VERSION 5.8 ;
BUSBITCHARS "[]" ;
DIVIDERCHAR "/" ;

PROPERTYDEFINITIONS
  LAYER LEF58_TYPE STRING ;
  LAYER LEF58_SPACING STRING ;
  LAYER LEF58_WIDTH STRING ;
END PROPERTYDEFINITIONS

UNITS
  DATABASE MICRONS 2000 ;
END UNITS
MANUFACTURINGGRID 0.0005 ;

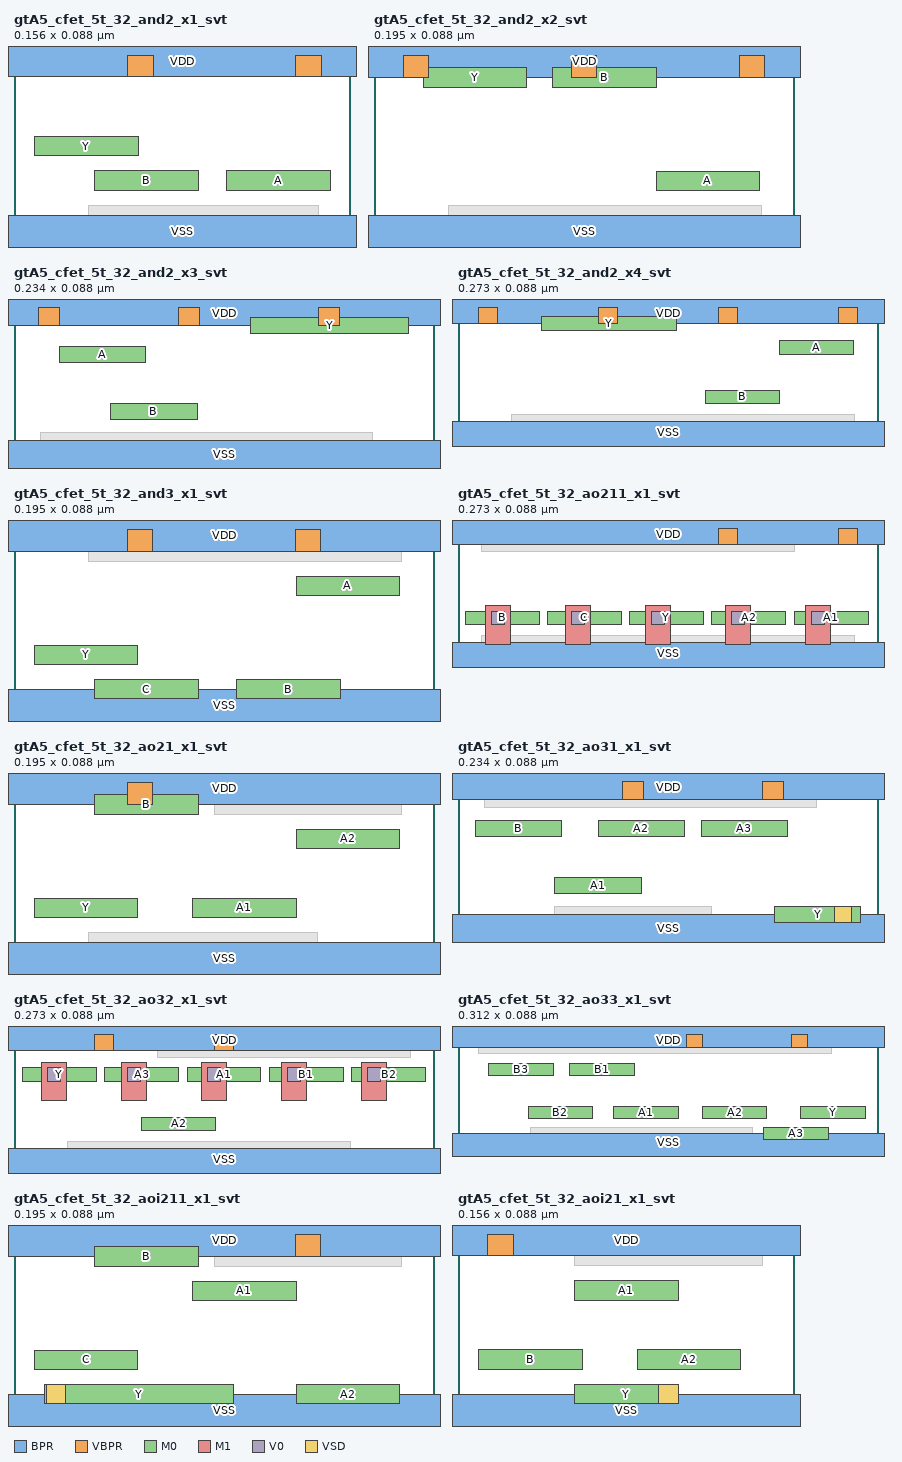
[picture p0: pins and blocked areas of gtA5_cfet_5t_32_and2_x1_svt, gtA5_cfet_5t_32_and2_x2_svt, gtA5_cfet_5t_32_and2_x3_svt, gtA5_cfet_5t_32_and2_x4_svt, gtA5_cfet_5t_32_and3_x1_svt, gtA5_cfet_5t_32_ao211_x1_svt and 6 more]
MACRO gtA5_cfet_5t_32_and2_x1_svt
  CLASS CORE ;
  ORIGIN 0 0 ;
  FOREIGN gtA5_cfet_5t_32_and2_x1_svt 0 0 ;
  SIZE 0.156 BY 0.088 ;
  SYMMETRY X Y ;
  SITE CORESITE_5t_32 ;
  PIN VDD
    DIRECTION INOUT ;
    USE POWER ;
    SHAPE ABUTMENT ;
    PORT
      LAYER BPR ;
        RECT -0.0225 0.076 0.1785 0.1 ;
      LAYER VBPR ;
        RECT 0.0525 0.076 0.0645 0.086 ;
        RECT 0.1305 0.076 0.1425 0.086 ;
    END
  END VDD
  PIN VSS
    DIRECTION INOUT ;
    USE GROUND ;
    SHAPE ABUTMENT ;
    PORT
      LAYER BPR ;
        RECT -0.0225 -0.012 0.1785 0.012 ;
    END
  END VSS
  PIN A
    DIRECTION INPUT ;
    USE SIGNAL ;
    PORT
      LAYER M0 ;
        RECT 0.0985 0.0235 0.1465 0.0325 ;
    END
  END A
  PIN B
    DIRECTION INPUT ;
    USE SIGNAL ;
    PORT
      LAYER M0 ;
        RECT 0.0375 0.0235 0.0855 0.0325 ;
    END
  END B
  PIN Y
    DIRECTION OUTPUT ;
    USE SIGNAL ;
    PORT
      LAYER M0 ;
        RECT 0.0095 0.0395 0.0575 0.0485 ;
    END
  END Y
  OBS
    LAYER VSD ;
      RECT 0.093 0.0075 0.102 0.0165 ;
    LAYER M0 ;
      RECT 0.0345 0.0075 0.141 0.0165 ;
  END
END gtA5_cfet_5t_32_and2_x1_svt

MACRO gtA5_cfet_5t_32_and2_x2_svt
  CLASS CORE ;
  ORIGIN 0 0 ;
  FOREIGN gtA5_cfet_5t_32_and2_x2_svt 0 0 ;
  SIZE 0.195 BY 0.088 ;
  SYMMETRY X Y ;
  SITE CORESITE_5t_32 ;
  PIN VDD
    DIRECTION INOUT ;
    USE POWER ;
    SHAPE ABUTMENT ;
    PORT
      LAYER BPR ;
        RECT -0.0225 0.076 0.2175 0.1 ;
      LAYER VBPR ;
        RECT 0.0135 0.076 0.0255 0.086 ;
        RECT 0.0915 0.076 0.1035 0.086 ;
        RECT 0.1695 0.076 0.1815 0.086 ;
    END
  END VDD
  PIN VSS
    DIRECTION INOUT ;
    USE GROUND ;
    SHAPE ABUTMENT ;
    PORT
      LAYER BPR ;
        RECT -0.0225 -0.012 0.2175 0.012 ;
    END
  END VSS
  PIN A
    DIRECTION INPUT ;
    USE SIGNAL ;
    PORT
      LAYER M0 ;
        RECT 0.131 0.0235 0.179 0.0325 ;
    END
  END A
  PIN B
    DIRECTION INPUT ;
    USE SIGNAL ;
    PORT
      LAYER M0 ;
        RECT 0.083 0.0715 0.131 0.0805 ;
    END
  END B
  PIN Y
    DIRECTION OUTPUT ;
    USE SIGNAL ;
    PORT
      LAYER M0 ;
        RECT 0.023 0.0715 0.071 0.0805 ;
    END
  END Y
  OBS
    LAYER VSD ;
      RECT 0.132 0.0075 0.141 0.0165 ;
    LAYER M0 ;
      RECT 0.0345 0.0075 0.18 0.0165 ;
  END
END gtA5_cfet_5t_32_and2_x2_svt

MACRO gtA5_cfet_5t_32_and2_x3_svt
  CLASS CORE ;
  ORIGIN 0 0 ;
  FOREIGN gtA5_cfet_5t_32_and2_x3_svt 0 0 ;
  SIZE 0.234 BY 0.088 ;
  SYMMETRY X Y ;
  SITE CORESITE_5t_32 ;
  PIN VDD
    DIRECTION INOUT ;
    USE POWER ;
    SHAPE ABUTMENT ;
    PORT
      LAYER BPR ;
        RECT -0.0225 0.076 0.2565 0.1 ;
      LAYER VBPR ;
        RECT 0.0135 0.076 0.0255 0.086 ;
        RECT 0.0915 0.076 0.1035 0.086 ;
        RECT 0.1695 0.076 0.1815 0.086 ;
    END
  END VDD
  PIN VSS
    DIRECTION INOUT ;
    USE GROUND ;
    SHAPE ABUTMENT ;
    PORT
      LAYER BPR ;
        RECT -0.0225 -0.012 0.2565 0.012 ;
    END
  END VSS
  PIN A
    DIRECTION INPUT ;
    USE SIGNAL ;
    PORT
      LAYER M0 ;
        RECT 0.0255 0.0555 0.0735 0.0645 ;
    END
  END A
  PIN B
    DIRECTION INPUT ;
    USE SIGNAL ;
    PORT
      LAYER M0 ;
        RECT 0.054 0.0235 0.102 0.0325 ;
    END
  END B
  PIN Y
    DIRECTION OUTPUT ;
    USE SIGNAL ;
    PORT
      LAYER M0 ;
        RECT 0.132 0.0715 0.22 0.0805 ;
    END
  END Y
  OBS
    LAYER VSD ;
      RECT 0.054 0.0075 0.063 0.0165 ;
    LAYER M0 ;
      RECT 0.015 0.0075 0.1995 0.0165 ;
  END
END gtA5_cfet_5t_32_and2_x3_svt

MACRO gtA5_cfet_5t_32_and2_x4_svt
  CLASS CORE ;
  ORIGIN 0 0 ;
  FOREIGN gtA5_cfet_5t_32_and2_x4_svt 0 0 ;
  SIZE 0.273 BY 0.088 ;
  SYMMETRY X Y ;
  SITE CORESITE_5t_32 ;
  PIN VDD
    DIRECTION INOUT ;
    USE POWER ;
    SHAPE ABUTMENT ;
    PORT
      LAYER BPR ;
        RECT -0.0225 0.076 0.2955 0.1 ;
      LAYER VBPR ;
        RECT 0.0135 0.076 0.0255 0.086 ;
        RECT 0.0915 0.076 0.1035 0.086 ;
        RECT 0.1695 0.076 0.1815 0.086 ;
        RECT 0.2475 0.076 0.2595 0.086 ;
    END
  END VDD
  PIN VSS
    DIRECTION INOUT ;
    USE GROUND ;
    SHAPE ABUTMENT ;
    PORT
      LAYER BPR ;
        RECT -0.0225 -0.012 0.2955 0.012 ;
    END
  END VSS
  PIN A
    DIRECTION INPUT ;
    USE SIGNAL ;
    PORT
      LAYER M0 ;
        RECT 0.209 0.0555 0.257 0.0645 ;
    END
  END A
  PIN B
    DIRECTION INPUT ;
    USE SIGNAL ;
    PORT
      LAYER M0 ;
        RECT 0.161 0.0235 0.209 0.0325 ;
    END
  END B
  PIN Y
    DIRECTION OUTPUT ;
    USE SIGNAL ;
    PORT
      LAYER M0 ;
        RECT 0.054 0.0715 0.142 0.0805 ;
    END
  END Y
  OBS
    LAYER VSD ;
      RECT 0.21 0.0075 0.219 0.0165 ;
    LAYER M0 ;
      RECT 0.0345 0.0075 0.258 0.0165 ;
  END
END gtA5_cfet_5t_32_and2_x4_svt

MACRO gtA5_cfet_5t_32_and3_x1_svt
  CLASS CORE ;
  ORIGIN 0 0 ;
  FOREIGN gtA5_cfet_5t_32_and3_x1_svt 0 0 ;
  SIZE 0.195 BY 0.088 ;
  SYMMETRY X Y ;
  SITE CORESITE_5t_32 ;
  PIN VDD
    DIRECTION INOUT ;
    USE POWER ;
    SHAPE ABUTMENT ;
    PORT
      LAYER BPR ;
        RECT -0.0225 0.076 0.2175 0.1 ;
      LAYER VBPR ;
        RECT 0.0525 0.076 0.0645 0.086 ;
        RECT 0.1305 0.076 0.1425 0.086 ;
    END
  END VDD
  PIN VSS
    DIRECTION INOUT ;
    USE GROUND ;
    SHAPE ABUTMENT ;
    PORT
      LAYER BPR ;
        RECT -0.0225 -0.012 0.2175 0.012 ;
    END
  END VSS
  PIN A
    DIRECTION INPUT ;
    USE SIGNAL ;
    PORT
      LAYER M0 ;
        RECT 0.131 0.0555 0.179 0.0645 ;
    END
  END A
  PIN B
    DIRECTION INPUT ;
    USE SIGNAL ;
    PORT
      LAYER M0 ;
        RECT 0.1035 0.0075 0.1515 0.0165 ;
    END
  END B
  PIN C
    DIRECTION INPUT ;
    USE SIGNAL ;
    PORT
      LAYER M0 ;
        RECT 0.0375 0.0075 0.0855 0.0165 ;
    END
  END C
  PIN Y
    DIRECTION OUTPUT ;
    USE SIGNAL ;
    PORT
      LAYER M0 ;
        RECT 0.0095 0.0235 0.0575 0.0325 ;
    END
  END Y
  OBS
    LAYER VSD ;
      RECT 0.093 0.0715 0.102 0.0805 ;
    LAYER M0 ;
      RECT 0.0345 0.0715 0.18 0.0805 ;
  END
END gtA5_cfet_5t_32_and3_x1_svt

MACRO gtA5_cfet_5t_32_ao211_x1_svt
  CLASS CORE ;
  ORIGIN 0 0 ;
  FOREIGN gtA5_cfet_5t_32_ao211_x1_svt 0 0 ;
  SIZE 0.273 BY 0.088 ;
  SYMMETRY X Y ;
  SITE CORESITE_5t_32 ;
  PIN VDD
    DIRECTION INOUT ;
    USE POWER ;
    SHAPE ABUTMENT ;
    PORT
      LAYER BPR ;
        RECT -0.0225 0.076 0.2955 0.1 ;
      LAYER VBPR ;
        RECT 0.1695 0.076 0.1815 0.086 ;
        RECT 0.2475 0.076 0.2595 0.086 ;
    END
  END VDD
  PIN VSS
    DIRECTION INOUT ;
    USE GROUND ;
    SHAPE ABUTMENT ;
    PORT
      LAYER BPR ;
        RECT -0.0225 -0.012 0.2955 0.012 ;
    END
  END VSS
  PIN A1
    DIRECTION INPUT ;
    USE SIGNAL ;
    PORT
      LAYER M0 ;
        RECT 0.2185 0.0235 0.2665 0.0325 ;
      LAYER M1 ;
        RECT 0.226 0.011 0.242 0.036 ;
      LAYER V0 ;
        RECT 0.2295 0.0235 0.2385 0.0325 ;
    END
  END A1
  PIN A2
    DIRECTION INPUT ;
    USE SIGNAL ;
    PORT
      LAYER M0 ;
        RECT 0.165 0.0235 0.213 0.0325 ;
      LAYER M1 ;
        RECT 0.174 0.011 0.19 0.036 ;
      LAYER V0 ;
        RECT 0.1775 0.0235 0.1865 0.0325 ;
    END
  END A2
  PIN B
    DIRECTION INPUT ;
    USE SIGNAL ;
    PORT
      LAYER M0 ;
        RECT 0.005 0.0235 0.053 0.0325 ;
      LAYER M1 ;
        RECT 0.018 0.011 0.034 0.036 ;
      LAYER V0 ;
        RECT 0.0215 0.0235 0.0305 0.0325 ;
    END
  END B
  PIN C
    DIRECTION INPUT ;
    USE SIGNAL ;
    PORT
      LAYER M0 ;
        RECT 0.058 0.0235 0.106 0.0325 ;
      LAYER M1 ;
        RECT 0.07 0.011 0.086 0.036 ;
      LAYER V0 ;
        RECT 0.0735 0.0235 0.0825 0.0325 ;
    END
  END C
  PIN Y
    DIRECTION OUTPUT ;
    USE SIGNAL ;
    PORT
      LAYER M0 ;
        RECT 0.1115 0.0235 0.1595 0.0325 ;
      LAYER M1 ;
        RECT 0.122 0.011 0.138 0.036 ;
      LAYER V0 ;
        RECT 0.1255 0.0235 0.1345 0.0325 ;
    END
  END Y
  OBS
    LAYER VSD ;
      RECT 0.21 0.0715 0.219 0.0805 ;
      RECT 0.093 0.0075 0.102 0.0165 ;
      RECT 0.015 0.0715 0.024 0.0805 ;
    LAYER M0 ;
      RECT 0.015 0.0075 0.258 0.0165 ;
      RECT 0.015 0.0715 0.219 0.0805 ;
  END
END gtA5_cfet_5t_32_ao211_x1_svt

MACRO gtA5_cfet_5t_32_ao21_x1_svt
  CLASS CORE ;
  ORIGIN 0 0 ;
  FOREIGN gtA5_cfet_5t_32_ao21_x1_svt 0 0 ;
  SIZE 0.195 BY 0.088 ;
  SYMMETRY X Y ;
  SITE CORESITE_5t_32 ;
  PIN VDD
    DIRECTION INOUT ;
    USE POWER ;
    SHAPE ABUTMENT ;
    PORT
      LAYER BPR ;
        RECT -0.0225 0.076 0.2175 0.1 ;
      LAYER VBPR ;
        RECT 0.0525 0.076 0.0645 0.086 ;
    END
  END VDD
  PIN VSS
    DIRECTION INOUT ;
    USE GROUND ;
    SHAPE ABUTMENT ;
    PORT
      LAYER BPR ;
        RECT -0.0225 -0.012 0.2175 0.012 ;
    END
  END VSS
  PIN A1
    DIRECTION INPUT ;
    USE SIGNAL ;
    PORT
      LAYER M0 ;
        RECT 0.083 0.0235 0.131 0.0325 ;
    END
  END A1
  PIN A2
    DIRECTION INPUT ;
    USE SIGNAL ;
    PORT
      LAYER M0 ;
        RECT 0.131 0.0555 0.179 0.0645 ;
    END
  END A2
  PIN B
    DIRECTION INPUT ;
    USE SIGNAL ;
    PORT
      LAYER M0 ;
        RECT 0.0375 0.0715 0.0855 0.0805 ;
    END
  END B
  PIN Y
    DIRECTION OUTPUT ;
    USE SIGNAL ;
    PORT
      LAYER M0 ;
        RECT 0.0095 0.0235 0.0575 0.0325 ;
    END
  END Y
  OBS
    LAYER VSD ;
      RECT 0.171 0.0715 0.18 0.0805 ;
      RECT 0.132 0.0075 0.141 0.0165 ;
      RECT 0.093 0.0715 0.102 0.0805 ;
    LAYER M0 ;
      RECT 0.093 0.0715 0.18 0.0805 ;
      RECT 0.0345 0.0075 0.141 0.0165 ;
  END
END gtA5_cfet_5t_32_ao21_x1_svt

MACRO gtA5_cfet_5t_32_ao31_x1_svt
  CLASS CORE ;
  ORIGIN 0 0 ;
  FOREIGN gtA5_cfet_5t_32_ao31_x1_svt 0 0 ;
  SIZE 0.234 BY 0.088 ;
  SYMMETRY X Y ;
  SITE CORESITE_5t_32 ;
  PIN VDD
    DIRECTION INOUT ;
    USE POWER ;
    SHAPE ABUTMENT ;
    PORT
      LAYER BPR ;
        RECT -0.0225 0.076 0.2565 0.1 ;
      LAYER VBPR ;
        RECT 0.0915 0.076 0.1035 0.086 ;
        RECT 0.1695 0.076 0.1815 0.086 ;
    END
  END VDD
  PIN VSS
    DIRECTION INOUT ;
    USE GROUND ;
    SHAPE ABUTMENT ;
    PORT
      LAYER BPR ;
        RECT -0.0225 -0.012 0.2565 0.012 ;
    END
  END VSS
  PIN A1
    DIRECTION INPUT ;
    USE SIGNAL ;
    PORT
      LAYER M0 ;
        RECT 0.054 0.0235 0.102 0.0325 ;
    END
  END A1
  PIN A2
    DIRECTION INPUT ;
    USE SIGNAL ;
    PORT
      LAYER M0 ;
        RECT 0.078 0.0555 0.126 0.0645 ;
    END
  END A2
  PIN A3
    DIRECTION INPUT ;
    USE SIGNAL ;
    PORT
      LAYER M0 ;
        RECT 0.1355 0.0555 0.1835 0.0645 ;
    END
  END A3
  PIN B
    DIRECTION INPUT ;
    USE SIGNAL ;
    PORT
      LAYER M0 ;
        RECT 0.0095 0.0555 0.0575 0.0645 ;
    END
  END B
  PIN Y
    DIRECTION OUTPUT ;
    USE SIGNAL ;
    PORT
      LAYER M0 ;
        RECT 0.1765 0.0075 0.2245 0.0165 ;
      LAYER VSD ;
        RECT 0.21 0.0075 0.219 0.0165 ;
    END
  END Y
  OBS
    LAYER VSD ;
      RECT 0.132 0.0075 0.141 0.0165 ;
      RECT 0.054 0.0075 0.063 0.0165 ;
      RECT 0.015 0.0715 0.024 0.0805 ;
    LAYER M0 ;
      RECT 0.015 0.0715 0.1995 0.0805 ;
      RECT 0.054 0.0075 0.141 0.0165 ;
  END
END gtA5_cfet_5t_32_ao31_x1_svt

MACRO gtA5_cfet_5t_32_ao32_x1_svt
  CLASS CORE ;
  ORIGIN 0 0 ;
  FOREIGN gtA5_cfet_5t_32_ao32_x1_svt 0 0 ;
  SIZE 0.273 BY 0.088 ;
  SYMMETRY X Y ;
  SITE CORESITE_5t_32 ;
  PIN VDD
    DIRECTION INOUT ;
    USE POWER ;
    SHAPE ABUTMENT ;
    PORT
      LAYER BPR ;
        RECT -0.0225 0.076 0.2955 0.1 ;
      LAYER VBPR ;
        RECT 0.0525 0.076 0.0645 0.086 ;
        RECT 0.1305 0.076 0.1425 0.086 ;
    END
  END VDD
  PIN VSS
    DIRECTION INOUT ;
    USE GROUND ;
    SHAPE ABUTMENT ;
    PORT
      LAYER BPR ;
        RECT -0.0225 -0.012 0.2955 0.012 ;
    END
  END VSS
  PIN A2
    DIRECTION INPUT ;
    USE SIGNAL ;
    PORT
      LAYER M0 ;
        RECT 0.083 0.0235 0.131 0.0325 ;
    END
  END A2
  PIN A1
    DIRECTION INPUT ;
    USE SIGNAL ;
    PORT
      LAYER M1 ;
        RECT 0.122 0.043 0.138 0.068 ;
      LAYER M0 ;
        RECT 0.1125 0.0555 0.1605 0.0645 ;
      LAYER V0 ;
        RECT 0.1255 0.0555 0.1345 0.0645 ;
    END
  END A1
  PIN A3
    DIRECTION INPUT ;
    USE SIGNAL ;
    PORT
      LAYER M1 ;
        RECT 0.07 0.043 0.086 0.068 ;
      LAYER M0 ;
        RECT 0.059 0.0555 0.107 0.0645 ;
      LAYER V0 ;
        RECT 0.0735 0.0555 0.0825 0.0645 ;
    END
  END A3
  PIN B1
    DIRECTION INPUT ;
    USE SIGNAL ;
    PORT
      LAYER M1 ;
        RECT 0.174 0.043 0.19 0.068 ;
      LAYER M0 ;
        RECT 0.166 0.0555 0.214 0.0645 ;
      LAYER V0 ;
        RECT 0.1775 0.0555 0.1865 0.0645 ;
    END
  END B1
  PIN B2
    DIRECTION INPUT ;
    USE SIGNAL ;
    PORT
      LAYER M1 ;
        RECT 0.226 0.043 0.242 0.068 ;
      LAYER M0 ;
        RECT 0.2195 0.0555 0.2675 0.0645 ;
      LAYER V0 ;
        RECT 0.2295 0.0555 0.2385 0.0645 ;
    END
  END B2
  PIN Y
    DIRECTION OUTPUT ;
    USE SIGNAL ;
    PORT
      LAYER M1 ;
        RECT 0.018 0.043 0.034 0.068 ;
      LAYER M0 ;
        RECT 0.0055 0.0555 0.0535 0.0645 ;
      LAYER V0 ;
        RECT 0.0215 0.0555 0.0305 0.0645 ;
    END
  END Y
  OBS
    LAYER VSD ;
      RECT 0.249 0.0715 0.258 0.0805 ;
      RECT 0.21 0.0075 0.219 0.0165 ;
      RECT 0.171 0.0715 0.18 0.0805 ;
      RECT 0.093 0.0715 0.102 0.0805 ;
    LAYER M0 ;
      RECT 0.093 0.0715 0.258 0.0805 ;
      RECT 0.0345 0.0075 0.219 0.0165 ;
  END
END gtA5_cfet_5t_32_ao32_x1_svt

MACRO gtA5_cfet_5t_32_ao33_x1_svt
  CLASS CORE ;
  ORIGIN 0 0 ;
  FOREIGN gtA5_cfet_5t_32_ao33_x1_svt 0 0 ;
  SIZE 0.312 BY 0.088 ;
  SYMMETRY X Y ;
  SITE CORESITE_5t_32 ;
  PIN VDD
    DIRECTION INOUT ;
    USE POWER ;
    SHAPE ABUTMENT ;
    PORT
      LAYER BPR ;
        RECT -0.0225 0.076 0.3345 0.1 ;
      LAYER VBPR ;
        RECT 0.1695 0.076 0.1815 0.086 ;
        RECT 0.2475 0.076 0.2595 0.086 ;
    END
  END VDD
  PIN VSS
    DIRECTION INOUT ;
    USE GROUND ;
    SHAPE ABUTMENT ;
    PORT
      LAYER BPR ;
        RECT -0.0225 -0.012 0.3345 0.012 ;
    END
  END VSS
  PIN A1
    DIRECTION INPUT ;
    USE SIGNAL ;
    PORT
      LAYER M0 ;
        RECT 0.1155 0.0235 0.1635 0.0325 ;
    END
  END A1
  PIN A2
    DIRECTION INPUT ;
    USE SIGNAL ;
    PORT
      LAYER M0 ;
        RECT 0.1815 0.0235 0.2295 0.0325 ;
    END
  END A2
  PIN A3
    DIRECTION INPUT ;
    USE SIGNAL ;
    PORT
      LAYER M0 ;
        RECT 0.227 0.0075 0.275 0.0165 ;
    END
  END A3
  PIN B1
    DIRECTION INPUT ;
    USE SIGNAL ;
    PORT
      LAYER M0 ;
        RECT 0.083 0.0555 0.131 0.0645 ;
    END
  END B1
  PIN B2
    DIRECTION INPUT ;
    USE SIGNAL ;
    PORT
      LAYER M0 ;
        RECT 0.052 0.0235 0.1 0.0325 ;
    END
  END B2
  PIN B3
    DIRECTION INPUT ;
    USE SIGNAL ;
    PORT
      LAYER M0 ;
        RECT 0.023 0.0555 0.071 0.0645 ;
    END
  END B3
  PIN Y
    DIRECTION OUTPUT ;
    USE SIGNAL ;
    PORT
      LAYER M0 ;
        RECT 0.2545 0.0235 0.3025 0.0325 ;
    END
  END Y
  OBS
    LAYER VSD ;
      RECT 0.21 0.0075 0.219 0.0165 ;
      RECT 0.132 0.0075 0.141 0.0165 ;
      RECT 0.093 0.0715 0.102 0.0805 ;
      RECT 0.054 0.0075 0.063 0.0165 ;
      RECT 0.015 0.0715 0.024 0.0805 ;
    LAYER M0 ;
      RECT 0.015 0.0715 0.2775 0.0805 ;
      RECT 0.054 0.0075 0.219 0.0165 ;
  END
END gtA5_cfet_5t_32_ao33_x1_svt

MACRO gtA5_cfet_5t_32_aoi211_x1_svt
  CLASS CORE ;
  ORIGIN 0 0 ;
  FOREIGN gtA5_cfet_5t_32_aoi211_x1_svt 0 0 ;
  SIZE 0.195 BY 0.088 ;
  SYMMETRY X Y ;
  SITE CORESITE_5t_32 ;
  PIN VDD
    DIRECTION INOUT ;
    USE POWER ;
    SHAPE ABUTMENT ;
    PORT
      LAYER BPR ;
        RECT -0.0225 0.076 0.2175 0.1 ;
      LAYER VBPR ;
        RECT 0.1305 0.076 0.1425 0.086 ;
    END
  END VDD
  PIN VSS
    DIRECTION INOUT ;
    USE GROUND ;
    SHAPE ABUTMENT ;
    PORT
      LAYER BPR ;
        RECT -0.0225 -0.012 0.2175 0.012 ;
    END
  END VSS
  PIN A1
    DIRECTION INPUT ;
    USE SIGNAL ;
    PORT
      LAYER M0 ;
        RECT 0.083 0.0555 0.131 0.0645 ;
    END
  END A1
  PIN A2
    DIRECTION INPUT ;
    USE SIGNAL ;
    PORT
      LAYER M0 ;
        RECT 0.131 0.0075 0.179 0.0165 ;
    END
  END A2
  PIN B
    DIRECTION INPUT ;
    USE SIGNAL ;
    PORT
      LAYER M0 ;
        RECT 0.0375 0.0715 0.0855 0.0805 ;
    END
  END B
  PIN C
    DIRECTION INPUT ;
    USE SIGNAL ;
    PORT
      LAYER M0 ;
        RECT 0.0095 0.0235 0.0575 0.0325 ;
    END
  END C
  PIN Y
    DIRECTION OUTPUT ;
    USE SIGNAL ;
    PORT
      LAYER M0 ;
        RECT 0.014 0.0075 0.102 0.0165 ;
      LAYER VSD ;
        RECT 0.015 0.0075 0.024 0.0165 ;
    END
  END Y
  OBS
    LAYER VSD ;
      RECT 0.171 0.0715 0.18 0.0805 ;
      RECT 0.093 0.0715 0.102 0.0805 ;
    LAYER M0 ;
      RECT 0.093 0.0715 0.18 0.0805 ;
  END
END gtA5_cfet_5t_32_aoi211_x1_svt

MACRO gtA5_cfet_5t_32_aoi21_x1_svt
  CLASS CORE ;
  ORIGIN 0 0 ;
  FOREIGN gtA5_cfet_5t_32_aoi21_x1_svt 0 0 ;
  SIZE 0.156 BY 0.088 ;
  SYMMETRY X Y ;
  SITE CORESITE_5t_32 ;
  PIN VDD
    DIRECTION INOUT ;
    USE POWER ;
    SHAPE ABUTMENT ;
    PORT
      LAYER BPR ;
        RECT -0.0225 0.076 0.1785 0.1 ;
      LAYER VBPR ;
        RECT 0.0135 0.076 0.0255 0.086 ;
    END
  END VDD
  PIN VSS
    DIRECTION INOUT ;
    USE GROUND ;
    SHAPE ABUTMENT ;
    PORT
      LAYER BPR ;
        RECT -0.0225 -0.012 0.1785 0.012 ;
    END
  END VSS
  PIN A1
    DIRECTION INPUT ;
    USE SIGNAL ;
    PORT
      LAYER M0 ;
        RECT 0.054 0.0555 0.102 0.0645 ;
    END
  END A1
  PIN A2
    DIRECTION INPUT ;
    USE SIGNAL ;
    PORT
      LAYER M0 ;
        RECT 0.083 0.0235 0.131 0.0325 ;
    END
  END A2
  PIN B
    DIRECTION INPUT ;
    USE SIGNAL ;
    PORT
      LAYER M0 ;
        RECT 0.0095 0.0235 0.0575 0.0325 ;
    END
  END B
  PIN Y
    DIRECTION OUTPUT ;
    USE SIGNAL ;
    PORT
      LAYER M0 ;
        RECT 0.054 0.0075 0.102 0.0165 ;
      LAYER VSD ;
        RECT 0.093 0.0075 0.102 0.0165 ;
    END
  END Y
  OBS
    LAYER VSD ;
      RECT 0.132 0.0715 0.141 0.0805 ;
      RECT 0.054 0.0715 0.063 0.0805 ;
    LAYER M0 ;
      RECT 0.054 0.0715 0.141 0.0805 ;
  END
END gtA5_cfet_5t_32_aoi21_x1_svt

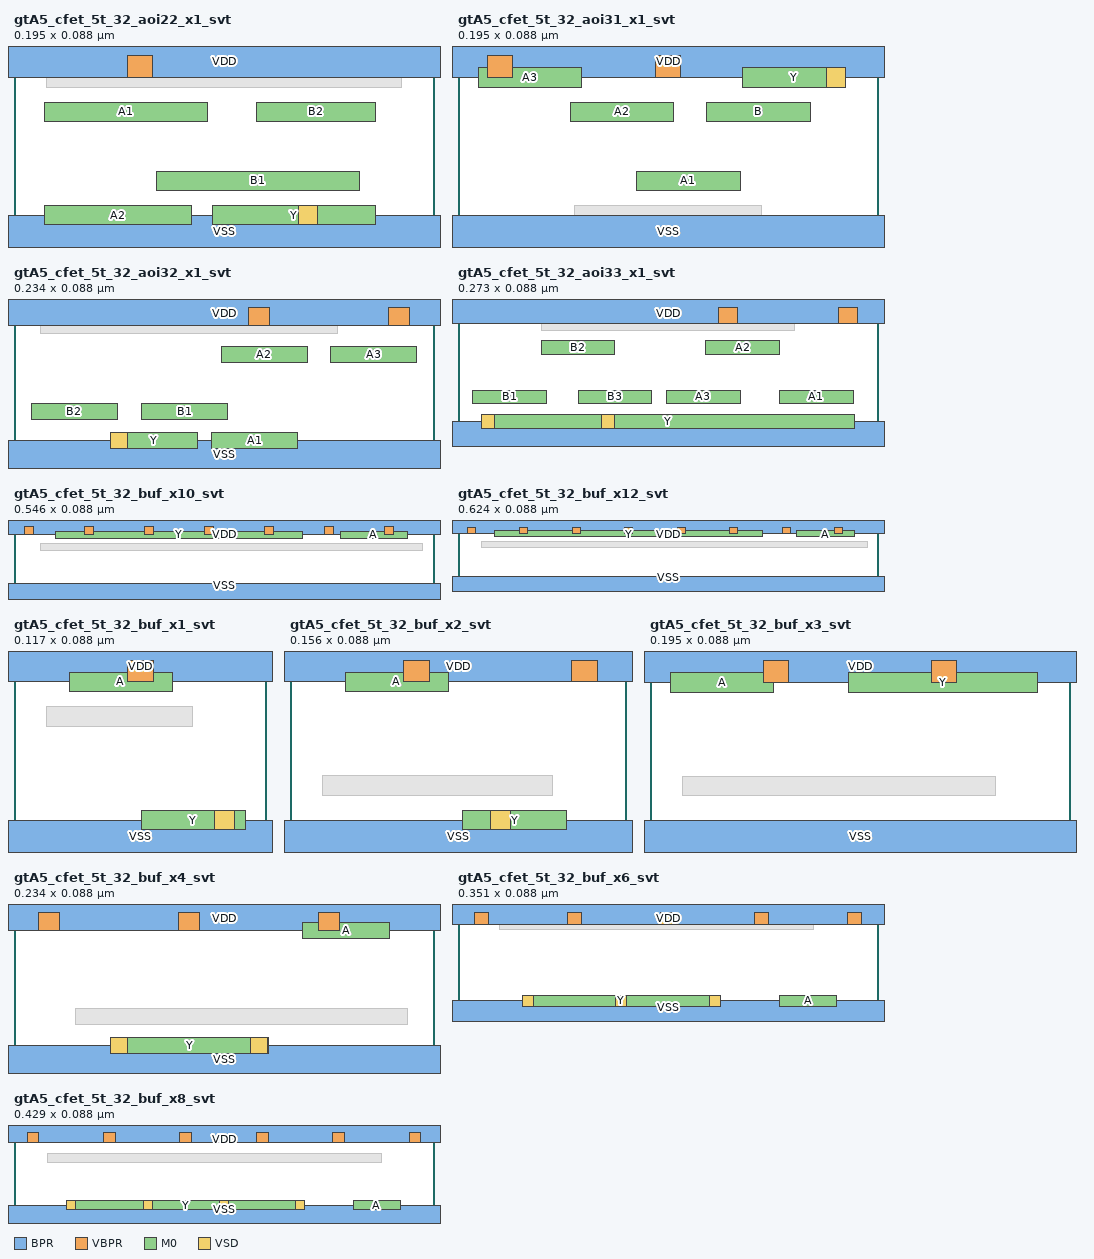
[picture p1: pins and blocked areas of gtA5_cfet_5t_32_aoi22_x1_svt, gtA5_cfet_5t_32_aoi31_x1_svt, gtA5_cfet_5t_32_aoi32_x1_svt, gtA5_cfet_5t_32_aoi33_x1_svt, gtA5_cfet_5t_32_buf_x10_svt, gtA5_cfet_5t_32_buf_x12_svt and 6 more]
MACRO gtA5_cfet_5t_32_aoi22_x1_svt
  CLASS CORE ;
  ORIGIN 0 0 ;
  FOREIGN gtA5_cfet_5t_32_aoi22_x1_svt 0 0 ;
  SIZE 0.195 BY 0.088 ;
  SYMMETRY X Y ;
  SITE CORESITE_5t_32 ;
  PIN VDD
    DIRECTION INOUT ;
    USE POWER ;
    SHAPE ABUTMENT ;
    PORT
      LAYER BPR ;
        RECT -0.0225 0.076 0.2175 0.1 ;
      LAYER VBPR ;
        RECT 0.0525 0.076 0.0645 0.086 ;
    END
  END VDD
  PIN VSS
    DIRECTION INOUT ;
    USE GROUND ;
    SHAPE ABUTMENT ;
    PORT
      LAYER BPR ;
        RECT -0.0225 -0.012 0.2175 0.012 ;
    END
  END VSS
  PIN A1
    DIRECTION INPUT ;
    USE SIGNAL ;
    PORT
      LAYER M0 ;
        RECT 0.014 0.0555 0.09 0.0645 ;
    END
  END A1
  PIN A2
    DIRECTION INPUT ;
    USE SIGNAL ;
    PORT
      LAYER M0 ;
        RECT 0.014 0.0075 0.0825 0.0165 ;
    END
  END A2
  PIN B1
    DIRECTION INPUT ;
    USE SIGNAL ;
    PORT
      LAYER M0 ;
        RECT 0.066 0.0235 0.1605 0.0325 ;
    END
  END B1
  PIN B2
    DIRECTION INPUT ;
    USE SIGNAL ;
    PORT
      LAYER M0 ;
        RECT 0.1125 0.0555 0.168 0.0645 ;
    END
  END B2
  PIN Y
    DIRECTION OUTPUT ;
    USE SIGNAL ;
    PORT
      LAYER M0 ;
        RECT 0.092 0.0075 0.168 0.0165 ;
      LAYER VSD ;
        RECT 0.132 0.0075 0.141 0.0165 ;
    END
  END Y
  OBS
    LAYER VSD ;
      RECT 0.171 0.0715 0.18 0.0805 ;
      RECT 0.093 0.0715 0.102 0.0805 ;
      RECT 0.015 0.0715 0.024 0.0805 ;
    LAYER M0 ;
      RECT 0.015 0.0715 0.18 0.0805 ;
  END
END gtA5_cfet_5t_32_aoi22_x1_svt

MACRO gtA5_cfet_5t_32_aoi31_x1_svt
  CLASS CORE ;
  ORIGIN 0 0 ;
  FOREIGN gtA5_cfet_5t_32_aoi31_x1_svt 0 0 ;
  SIZE 0.195 BY 0.088 ;
  SYMMETRY X Y ;
  SITE CORESITE_5t_32 ;
  PIN VDD
    DIRECTION INOUT ;
    USE POWER ;
    SHAPE ABUTMENT ;
    PORT
      LAYER BPR ;
        RECT -0.0225 0.076 0.2175 0.1 ;
      LAYER VBPR ;
        RECT 0.0135 0.076 0.0255 0.086 ;
        RECT 0.0915 0.076 0.1035 0.086 ;
    END
  END VDD
  PIN VSS
    DIRECTION INOUT ;
    USE GROUND ;
    SHAPE ABUTMENT ;
    PORT
      LAYER BPR ;
        RECT -0.0225 -0.012 0.2175 0.012 ;
    END
  END VSS
  PIN A1
    DIRECTION INPUT ;
    USE SIGNAL ;
    PORT
      LAYER M0 ;
        RECT 0.083 0.0235 0.131 0.0325 ;
    END
  END A1
  PIN A2
    DIRECTION INPUT ;
    USE SIGNAL ;
    PORT
      LAYER M0 ;
        RECT 0.052 0.0555 0.1 0.0645 ;
    END
  END A2
  PIN A3
    DIRECTION INPUT ;
    USE SIGNAL ;
    PORT
      LAYER M0 ;
        RECT 0.0095 0.0715 0.0575 0.0805 ;
    END
  END A3
  PIN B
    DIRECTION INPUT ;
    USE SIGNAL ;
    PORT
      LAYER M0 ;
        RECT 0.1155 0.0555 0.1635 0.0645 ;
    END
  END B
  PIN Y
    DIRECTION OUTPUT ;
    USE SIGNAL ;
    PORT
      LAYER M0 ;
        RECT 0.132 0.0715 0.18 0.0805 ;
      LAYER VSD ;
        RECT 0.171 0.0715 0.18 0.0805 ;
    END
  END Y
  OBS
    LAYER VSD ;
      RECT 0.132 0.0075 0.141 0.0165 ;
      RECT 0.054 0.0075 0.063 0.0165 ;
    LAYER M0 ;
      RECT 0.054 0.0075 0.141 0.0165 ;
  END
END gtA5_cfet_5t_32_aoi31_x1_svt

MACRO gtA5_cfet_5t_32_aoi32_x1_svt
  CLASS CORE ;
  ORIGIN 0 0 ;
  FOREIGN gtA5_cfet_5t_32_aoi32_x1_svt 0 0 ;
  SIZE 0.234 BY 0.088 ;
  SYMMETRY X Y ;
  SITE CORESITE_5t_32 ;
  PIN VDD
    DIRECTION INOUT ;
    USE POWER ;
    SHAPE ABUTMENT ;
    PORT
      LAYER BPR ;
        RECT -0.0225 0.076 0.2565 0.1 ;
      LAYER VBPR ;
        RECT 0.1305 0.076 0.1425 0.086 ;
        RECT 0.2085 0.076 0.2205 0.086 ;
    END
  END VDD
  PIN VSS
    DIRECTION INOUT ;
    USE GROUND ;
    SHAPE ABUTMENT ;
    PORT
      LAYER BPR ;
        RECT -0.0225 -0.012 0.2565 0.012 ;
    END
  END VSS
  PIN A1
    DIRECTION INPUT ;
    USE SIGNAL ;
    PORT
      LAYER M0 ;
        RECT 0.11 0.0075 0.158 0.0165 ;
    END
  END A1
  PIN A2
    DIRECTION INPUT ;
    USE SIGNAL ;
    PORT
      LAYER M0 ;
        RECT 0.1155 0.0555 0.1635 0.0645 ;
    END
  END A2
  PIN A3
    DIRECTION INPUT ;
    USE SIGNAL ;
    PORT
      LAYER M0 ;
        RECT 0.1765 0.0555 0.2245 0.0645 ;
    END
  END A3
  PIN B1
    DIRECTION INPUT ;
    USE SIGNAL ;
    PORT
      LAYER M0 ;
        RECT 0.071 0.0235 0.119 0.0325 ;
    END
  END B1
  PIN B2
    DIRECTION INPUT ;
    USE SIGNAL ;
    PORT
      LAYER M0 ;
        RECT 0.0095 0.0235 0.0575 0.0325 ;
    END
  END B2
  PIN Y
    DIRECTION OUTPUT ;
    USE SIGNAL ;
    PORT
      LAYER M0 ;
        RECT 0.054 0.0075 0.102 0.0165 ;
      LAYER VSD ;
        RECT 0.054 0.0075 0.063 0.0165 ;
    END
  END Y
  OBS
    LAYER VSD ;
      RECT 0.171 0.0715 0.18 0.0805 ;
      RECT 0.093 0.0715 0.102 0.0805 ;
      RECT 0.015 0.0715 0.024 0.0805 ;
    LAYER M0 ;
      RECT 0.015 0.0715 0.18 0.0805 ;
  END
END gtA5_cfet_5t_32_aoi32_x1_svt

MACRO gtA5_cfet_5t_32_aoi33_x1_svt
  CLASS CORE ;
  ORIGIN 0 0 ;
  FOREIGN gtA5_cfet_5t_32_aoi33_x1_svt 0 0 ;
  SIZE 0.273 BY 0.088 ;
  SYMMETRY X Y ;
  SITE CORESITE_5t_32 ;
  PIN VDD
    DIRECTION INOUT ;
    USE POWER ;
    SHAPE ABUTMENT ;
    PORT
      LAYER BPR ;
        RECT -0.0225 0.076 0.2955 0.1 ;
      LAYER VBPR ;
        RECT 0.1695 0.076 0.1815 0.086 ;
        RECT 0.2475 0.076 0.2595 0.086 ;
    END
  END VDD
  PIN VSS
    DIRECTION INOUT ;
    USE GROUND ;
    SHAPE ABUTMENT ;
    PORT
      LAYER BPR ;
        RECT -0.0225 -0.012 0.2955 0.012 ;
    END
  END VSS
  PIN A1
    DIRECTION INPUT ;
    USE SIGNAL ;
    PORT
      LAYER M0 ;
        RECT 0.209 0.0235 0.257 0.0325 ;
    END
  END A1
  PIN A2
    DIRECTION INPUT ;
    USE SIGNAL ;
    PORT
      LAYER M0 ;
        RECT 0.161 0.0555 0.209 0.0645 ;
    END
  END A2
  PIN A3
    DIRECTION INPUT ;
    USE SIGNAL ;
    PORT
      LAYER M0 ;
        RECT 0.1355 0.0235 0.1835 0.0325 ;
    END
  END A3
  PIN B1
    DIRECTION INPUT ;
    USE SIGNAL ;
    PORT
      LAYER M0 ;
        RECT 0.0095 0.0235 0.0575 0.0325 ;
    END
  END B1
  PIN B2
    DIRECTION INPUT ;
    USE SIGNAL ;
    PORT
      LAYER M0 ;
        RECT 0.054 0.0555 0.102 0.0645 ;
    END
  END B2
  PIN B3
    DIRECTION INPUT ;
    USE SIGNAL ;
    PORT
      LAYER M0 ;
        RECT 0.078 0.0235 0.126 0.0325 ;
    END
  END B3
  PIN Y
    DIRECTION OUTPUT ;
    USE SIGNAL ;
    PORT
      LAYER M0 ;
        RECT 0.015 0.0075 0.258 0.0165 ;
      LAYER VSD ;
        RECT 0.015 0.0075 0.024 0.0165 ;
        RECT 0.093 0.0075 0.102 0.0165 ;
    END
  END Y
  OBS
    LAYER VSD ;
      RECT 0.21 0.0715 0.219 0.0805 ;
      RECT 0.132 0.0715 0.141 0.0805 ;
      RECT 0.054 0.0715 0.063 0.0805 ;
    LAYER M0 ;
      RECT 0.054 0.0715 0.219 0.0805 ;
  END
END gtA5_cfet_5t_32_aoi33_x1_svt

MACRO gtA5_cfet_5t_32_buf_x10_svt
  CLASS CORE ;
  ORIGIN 0 0 ;
  FOREIGN gtA5_cfet_5t_32_buf_x10_svt 0 0 ;
  SIZE 0.546 BY 0.088 ;
  SYMMETRY X Y ;
  SITE CORESITE_5t_32 ;
  PIN VDD
    DIRECTION INOUT ;
    USE POWER ;
    SHAPE ABUTMENT ;
    PORT
      LAYER BPR ;
        RECT -0.0225 0.076 0.5685 0.1 ;
      LAYER VBPR ;
        RECT 0.0135 0.076 0.0255 0.086 ;
        RECT 0.0915 0.076 0.1035 0.086 ;
        RECT 0.1695 0.076 0.1815 0.086 ;
        RECT 0.2475 0.076 0.2595 0.086 ;
        RECT 0.3255 0.076 0.3375 0.086 ;
        RECT 0.4035 0.076 0.4155 0.086 ;
        RECT 0.4815 0.076 0.4935 0.086 ;
    END
  END VDD
  PIN VSS
    DIRECTION INOUT ;
    USE GROUND ;
    SHAPE ABUTMENT ;
    PORT
      LAYER BPR ;
        RECT -0.0225 -0.012 0.5685 0.012 ;
    END
  END VSS
  PIN A
    DIRECTION INPUT ;
    USE SIGNAL ;
    PORT
      LAYER M0 ;
        RECT 0.4245 0.0715 0.5115 0.0805 ;
    END
  END A
  PIN Y
    DIRECTION OUTPUT ;
    USE SIGNAL ;
    PORT
      LAYER M0 ;
        RECT 0.054 0.0715 0.375 0.0805 ;
    END
  END Y
  OBS
    LAYER M0 ;
      RECT 0.0345 0.0555 0.531 0.0645 ;
  END
END gtA5_cfet_5t_32_buf_x10_svt

MACRO gtA5_cfet_5t_32_buf_x12_svt
  CLASS CORE ;
  ORIGIN 0 0 ;
  FOREIGN gtA5_cfet_5t_32_buf_x12_svt 0 0 ;
  SIZE 0.624 BY 0.088 ;
  SYMMETRY X Y ;
  SITE CORESITE_5t_32 ;
  PIN VDD
    DIRECTION INOUT ;
    USE POWER ;
    SHAPE ABUTMENT ;
    PORT
      LAYER BPR ;
        RECT -0.0225 0.076 0.6465 0.1 ;
      LAYER VBPR ;
        RECT 0.0135 0.076 0.0255 0.086 ;
        RECT 0.0915 0.076 0.1035 0.086 ;
        RECT 0.1695 0.076 0.1815 0.086 ;
        RECT 0.2475 0.076 0.2595 0.086 ;
        RECT 0.3255 0.076 0.3375 0.086 ;
        RECT 0.4035 0.076 0.4155 0.086 ;
        RECT 0.4815 0.076 0.4935 0.086 ;
        RECT 0.5595 0.076 0.5715 0.086 ;
    END
  END VDD
  PIN VSS
    DIRECTION INOUT ;
    USE GROUND ;
    SHAPE ABUTMENT ;
    PORT
      LAYER BPR ;
        RECT -0.0225 -0.012 0.6465 0.012 ;
    END
  END VSS
  PIN A
    DIRECTION INPUT ;
    USE SIGNAL ;
    PORT
      LAYER M0 ;
        RECT 0.5025 0.0715 0.5895 0.0805 ;
    END
  END A
  PIN Y
    DIRECTION OUTPUT ;
    USE SIGNAL ;
    PORT
      LAYER M0 ;
        RECT 0.054 0.0715 0.453 0.0805 ;
    END
  END Y
  OBS
    LAYER M0 ;
      RECT 0.0345 0.0555 0.609 0.0645 ;
  END
END gtA5_cfet_5t_32_buf_x12_svt

MACRO gtA5_cfet_5t_32_buf_x1_svt
  CLASS CORE ;
  ORIGIN 0 0 ;
  FOREIGN gtA5_cfet_5t_32_buf_x1_svt 0 0 ;
  SIZE 0.117 BY 0.088 ;
  SYMMETRY X Y ;
  SITE CORESITE_5t_32 ;
  PIN VDD
    DIRECTION INOUT ;
    USE POWER ;
    SHAPE ABUTMENT ;
    PORT
      LAYER BPR ;
        RECT -0.0225 0.076 0.1395 0.1 ;
      LAYER VBPR ;
        RECT 0.0525 0.076 0.0645 0.086 ;
    END
  END VDD
  PIN VSS
    DIRECTION INOUT ;
    USE GROUND ;
    SHAPE ABUTMENT ;
    PORT
      LAYER BPR ;
        RECT -0.0225 -0.012 0.1395 0.012 ;
    END
  END VSS
  PIN A
    DIRECTION INPUT ;
    USE SIGNAL ;
    PORT
      LAYER M0 ;
        RECT 0.0255 0.0715 0.0735 0.0805 ;
    END
  END A
  PIN Y
    DIRECTION OUTPUT ;
    USE SIGNAL ;
    PORT
      LAYER M0 ;
        RECT 0.059 0.0075 0.107 0.0165 ;
      LAYER VSD ;
        RECT 0.093 0.0075 0.102 0.0165 ;
    END
  END Y
  OBS
    LAYER M0 ;
      RECT 0.015 0.0555 0.0825 0.0645 ;
  END
END gtA5_cfet_5t_32_buf_x1_svt

MACRO gtA5_cfet_5t_32_buf_x2_svt
  CLASS CORE ;
  ORIGIN 0 0 ;
  FOREIGN gtA5_cfet_5t_32_buf_x2_svt 0 0 ;
  SIZE 0.156 BY 0.088 ;
  SYMMETRY X Y ;
  SITE CORESITE_5t_32 ;
  PIN VDD
    DIRECTION INOUT ;
    USE POWER ;
    SHAPE ABUTMENT ;
    PORT
      LAYER BPR ;
        RECT -0.0225 0.076 0.1785 0.1 ;
      LAYER VBPR ;
        RECT 0.0525 0.076 0.0645 0.086 ;
        RECT 0.1305 0.076 0.1425 0.086 ;
    END
  END VDD
  PIN VSS
    DIRECTION INOUT ;
    USE GROUND ;
    SHAPE ABUTMENT ;
    PORT
      LAYER BPR ;
        RECT -0.0225 -0.012 0.1785 0.012 ;
    END
  END VSS
  PIN A
    DIRECTION INPUT ;
    USE SIGNAL ;
    PORT
      LAYER M0 ;
        RECT 0.0255 0.0715 0.0735 0.0805 ;
    END
  END A
  PIN Y
    DIRECTION OUTPUT ;
    USE SIGNAL ;
    PORT
      LAYER M0 ;
        RECT 0.08 0.0075 0.128 0.0165 ;
      LAYER VSD ;
        RECT 0.093 0.0075 0.102 0.0165 ;
    END
  END Y
  OBS
    LAYER M0 ;
      RECT 0.015 0.0235 0.1215 0.0325 ;
  END
END gtA5_cfet_5t_32_buf_x2_svt

MACRO gtA5_cfet_5t_32_buf_x3_svt
  CLASS CORE ;
  ORIGIN 0 0 ;
  FOREIGN gtA5_cfet_5t_32_buf_x3_svt 0 0 ;
  SIZE 0.195 BY 0.088 ;
  SYMMETRY X Y ;
  SITE CORESITE_5t_32 ;
  PIN VDD
    DIRECTION INOUT ;
    USE POWER ;
    SHAPE ABUTMENT ;
    PORT
      LAYER BPR ;
        RECT -0.0225 0.076 0.2175 0.1 ;
      LAYER VBPR ;
        RECT 0.0525 0.076 0.0645 0.086 ;
        RECT 0.1305 0.076 0.1425 0.086 ;
    END
  END VDD
  PIN VSS
    DIRECTION INOUT ;
    USE GROUND ;
    SHAPE ABUTMENT ;
    PORT
      LAYER BPR ;
        RECT -0.0225 -0.012 0.2175 0.012 ;
    END
  END VSS
  PIN A
    DIRECTION INPUT ;
    USE SIGNAL ;
    PORT
      LAYER M0 ;
        RECT 0.0095 0.0715 0.0575 0.0805 ;
    END
  END A
  PIN Y
    DIRECTION OUTPUT ;
    USE SIGNAL ;
    PORT
      LAYER M0 ;
        RECT 0.092 0.0715 0.18 0.0805 ;
    END
  END Y
  OBS
    LAYER M0 ;
      RECT 0.015 0.0235 0.1605 0.0325 ;
  END
END gtA5_cfet_5t_32_buf_x3_svt

MACRO gtA5_cfet_5t_32_buf_x4_svt
  CLASS CORE ;
  ORIGIN 0 0 ;
  FOREIGN gtA5_cfet_5t_32_buf_x4_svt 0 0 ;
  SIZE 0.234 BY 0.088 ;
  SYMMETRY X Y ;
  SITE CORESITE_5t_32 ;
  PIN VDD
    DIRECTION INOUT ;
    USE POWER ;
    SHAPE ABUTMENT ;
    PORT
      LAYER BPR ;
        RECT -0.0225 0.076 0.2565 0.1 ;
      LAYER VBPR ;
        RECT 0.0135 0.076 0.0255 0.086 ;
        RECT 0.0915 0.076 0.1035 0.086 ;
        RECT 0.1695 0.076 0.1815 0.086 ;
    END
  END VDD
  PIN VSS
    DIRECTION INOUT ;
    USE GROUND ;
    SHAPE ABUTMENT ;
    PORT
      LAYER BPR ;
        RECT -0.0225 -0.012 0.2565 0.012 ;
    END
  END VSS
  PIN A
    DIRECTION INPUT ;
    USE SIGNAL ;
    PORT
      LAYER M0 ;
        RECT 0.161 0.0715 0.209 0.0805 ;
    END
  END A
  PIN Y
    DIRECTION OUTPUT ;
    USE SIGNAL ;
    PORT
      LAYER M0 ;
        RECT 0.054 0.0075 0.142 0.0165 ;
      LAYER VSD ;
        RECT 0.054 0.0075 0.063 0.0165 ;
        RECT 0.132 0.0075 0.141 0.0165 ;
    END
  END Y
  OBS
    LAYER M0 ;
      RECT 0.0345 0.0235 0.219 0.0325 ;
  END
END gtA5_cfet_5t_32_buf_x4_svt

MACRO gtA5_cfet_5t_32_buf_x6_svt
  CLASS CORE ;
  ORIGIN 0 0 ;
  FOREIGN gtA5_cfet_5t_32_buf_x6_svt 0 0 ;
  SIZE 0.351 BY 0.088 ;
  SYMMETRY X Y ;
  SITE CORESITE_5t_32 ;
  PIN VDD
    DIRECTION INOUT ;
    USE POWER ;
    SHAPE ABUTMENT ;
    PORT
      LAYER BPR ;
        RECT -0.0225 0.076 0.3735 0.1 ;
      LAYER VBPR ;
        RECT 0.0135 0.076 0.0255 0.086 ;
        RECT 0.0915 0.076 0.1035 0.086 ;
        RECT 0.1695 0.076 0.1815 0.086 ;
        RECT 0.2475 0.076 0.2595 0.086 ;
        RECT 0.3255 0.076 0.3375 0.086 ;
    END
  END VDD
  PIN VSS
    DIRECTION INOUT ;
    USE GROUND ;
    SHAPE ABUTMENT ;
    PORT
      LAYER BPR ;
        RECT -0.0225 -0.012 0.3735 0.012 ;
    END
  END VSS
  PIN A
    DIRECTION INPUT ;
    USE SIGNAL ;
    PORT
      LAYER M0 ;
        RECT 0.2685 0.0075 0.3165 0.0165 ;
    END
  END A
  PIN Y
    DIRECTION OUTPUT ;
    USE SIGNAL ;
    PORT
      LAYER M0 ;
        RECT 0.054 0.0075 0.219 0.0165 ;
      LAYER VSD ;
        RECT 0.054 0.0075 0.063 0.0165 ;
        RECT 0.132 0.0075 0.141 0.0165 ;
        RECT 0.21 0.0075 0.219 0.0165 ;
    END
  END Y
  OBS
    LAYER M0 ;
      RECT 0.0345 0.0715 0.297 0.0805 ;
  END
END gtA5_cfet_5t_32_buf_x6_svt

MACRO gtA5_cfet_5t_32_buf_x8_svt
  CLASS CORE ;
  ORIGIN 0 0 ;
  FOREIGN gtA5_cfet_5t_32_buf_x8_svt 0 0 ;
  SIZE 0.429 BY 0.088 ;
  SYMMETRY X Y ;
  SITE CORESITE_5t_32 ;
  PIN VDD
    DIRECTION INOUT ;
    USE POWER ;
    SHAPE ABUTMENT ;
    PORT
      LAYER BPR ;
        RECT -0.0225 0.076 0.4515 0.1 ;
      LAYER VBPR ;
        RECT 0.0135 0.076 0.0255 0.086 ;
        RECT 0.0915 0.076 0.1035 0.086 ;
        RECT 0.1695 0.076 0.1815 0.086 ;
        RECT 0.2475 0.076 0.2595 0.086 ;
        RECT 0.3255 0.076 0.3375 0.086 ;
        RECT 0.4035 0.076 0.4155 0.086 ;
    END
  END VDD
  PIN VSS
    DIRECTION INOUT ;
    USE GROUND ;
    SHAPE ABUTMENT ;
    PORT
      LAYER BPR ;
        RECT -0.0225 -0.012 0.4515 0.012 ;
    END
  END VSS
  PIN A
    DIRECTION INPUT ;
    USE SIGNAL ;
    PORT
      LAYER M0 ;
        RECT 0.3465 0.0075 0.3945 0.0165 ;
    END
  END A
  PIN Y
    DIRECTION OUTPUT ;
    USE SIGNAL ;
    PORT
      LAYER M0 ;
        RECT 0.054 0.0075 0.297 0.0165 ;
      LAYER VSD ;
        RECT 0.054 0.0075 0.063 0.0165 ;
        RECT 0.132 0.0075 0.141 0.0165 ;
        RECT 0.21 0.0075 0.219 0.0165 ;
        RECT 0.288 0.0075 0.297 0.0165 ;
    END
  END Y
  OBS
    LAYER M0 ;
      RECT 0.0345 0.0555 0.375 0.0645 ;
  END
END gtA5_cfet_5t_32_buf_x8_svt

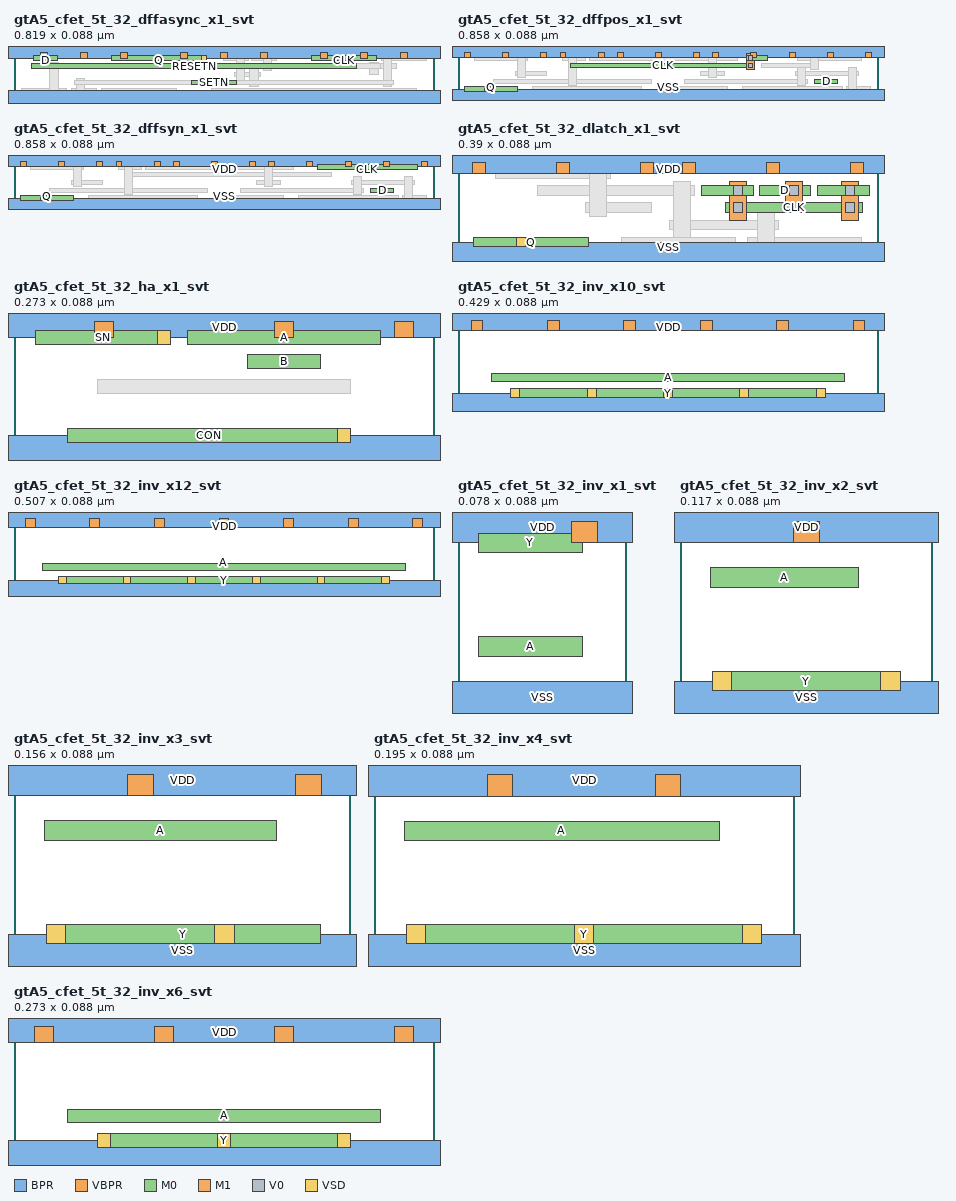
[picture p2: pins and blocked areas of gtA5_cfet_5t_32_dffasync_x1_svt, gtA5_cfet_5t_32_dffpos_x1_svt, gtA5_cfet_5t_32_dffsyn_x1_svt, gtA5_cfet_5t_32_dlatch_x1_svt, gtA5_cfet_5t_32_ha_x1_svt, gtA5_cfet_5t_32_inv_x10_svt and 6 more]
MACRO gtA5_cfet_5t_32_dffasync_x1_svt
  CLASS CORE ;
  ORIGIN 0 0 ;
  FOREIGN gtA5_cfet_5t_32_dffasync_x1_svt 0 0 ;
  SIZE 0.819 BY 0.088 ;
  SYMMETRY X Y ;
  SITE CORESITE_5t_32 ;
  PIN VDD
    DIRECTION INOUT ;
    USE POWER ;
    SHAPE ABUTMENT ;
    PORT
      LAYER BPR ;
        RECT -0.0225 0.076 0.8415 0.1 ;
      LAYER VBPR ;
        RECT 0.0525 0.076 0.0645 0.086 ;
        RECT 0.1305 0.076 0.1425 0.086 ;
        RECT 0.2085 0.076 0.2205 0.086 ;
        RECT 0.3255 0.076 0.3375 0.086 ;
        RECT 0.4035 0.076 0.4155 0.086 ;
        RECT 0.4815 0.076 0.4935 0.086 ;
        RECT 0.5985 0.076 0.6105 0.086 ;
        RECT 0.6765 0.076 0.6885 0.086 ;
        RECT 0.7545 0.076 0.7665 0.086 ;
    END
  END VDD
  PIN VSS
    DIRECTION INOUT ;
    USE GROUND ;
    SHAPE ABUTMENT ;
    PORT
      LAYER BPR ;
        RECT -0.0225 -0.012 0.8415 0.012 ;
    END
  END VSS
  PIN CLK
    DIRECTION INPUT ;
    USE CLOCK ;
    PORT
      LAYER M0 ;
        RECT 0.5805 0.0715 0.7065 0.0805 ;
    END
  END CLK
  PIN D
    DIRECTION INPUT ;
    USE SIGNAL ;
    PORT
      LAYER M0 ;
        RECT 0.0375 0.0715 0.0855 0.0805 ;
    END
  END D
  PIN Q
    DIRECTION OUTPUT ;
    USE SIGNAL ;
    PORT
      LAYER M0 ;
        RECT 0.1905 0.0715 0.375 0.0805 ;
      LAYER VSD ;
        RECT 0.366 0.0715 0.375 0.0805 ;
    END
  END Q
  PIN RESETN
    DIRECTION INPUT ;
    USE SIGNAL ;
    PORT
      LAYER M0 ;
        RECT 0.0345 0.0555 0.6675 0.0645 ;
    END
  END RESETN
  PIN SETN
    DIRECTION INPUT ;
    USE SIGNAL ;
    PORT
      LAYER M0 ;
        RECT 0.3465 0.0235 0.4335 0.0325 ;
    END
  END SETN
  OBS
    LAYER VSD ;
      RECT 0.717 0.0715 0.726 0.0805 ;
      RECT 0.639 0.0075 0.648 0.0165 ;
      RECT 0.561 0.0075 0.57 0.0165 ;
      RECT 0.444 0.0715 0.453 0.0805 ;
      RECT 0.249 0.0075 0.258 0.0165 ;
      RECT 0.171 0.0075 0.18 0.0165 ;
      RECT 0.093 0.0075 0.102 0.0165 ;
      RECT 0.015 0.0075 0.024 0.0165 ;
    LAYER M0 ;
      RECT 0.716 0.0715 0.804 0.0805 ;
      RECT 0.3855 0.0075 0.7845 0.0165 ;
      RECT 0.69 0.0555 0.7455 0.0645 ;
      RECT 0.456 0.0235 0.6285 0.0325 ;
      RECT 0.4635 0.0715 0.5115 0.0805 ;
      RECT 0.43 0.0395 0.48 0.0485 ;
      RECT 0.4085 0.0715 0.4565 0.0805 ;
      RECT 0.171 0.0075 0.3165 0.0165 ;
      RECT 0.1125 0.0075 0.1605 0.0165 ;
      RECT 0.015 0.0075 0.102 0.0165 ;
    LAYER V0 ;
      RECT 0.7235 0.0715 0.7325 0.0805 ;
      RECT 0.6975 0.0555 0.7065 0.0645 ;
      RECT 0.4895 0.0715 0.4985 0.0805 ;
      RECT 0.4635 0.0235 0.4725 0.0325 ;
      RECT 0.4635 0.0395 0.4725 0.0485 ;
      RECT 0.4375 0.0395 0.4465 0.0485 ;
      RECT 0.4375 0.0715 0.4465 0.0805 ;
      RECT 0.1255 0.0075 0.1345 0.0165 ;
      RECT 0.0735 0.0075 0.0825 0.0165 ;
    LAYER M1 ;
      RECT 0.72 0.02 0.736 0.084 ;
      RECT 0.694 0.043 0.71 0.068 ;
      RECT 0.486 0.052 0.502 0.084 ;
      RECT 0.46 0.02 0.476 0.056 ;
      RECT 0.434 0.032 0.45 0.084 ;
      RECT 0.122 0.004 0.138 0.036 ;
      RECT 0.07 0.004 0.086 0.068 ;
    LAYER V1 ;
      RECT 0.7235 0.0235 0.7325 0.0325 ;
      RECT 0.6975 0.0555 0.7065 0.0645 ;
      RECT 0.4895 0.0555 0.4985 0.0645 ;
      RECT 0.1255 0.0235 0.1345 0.0325 ;
      RECT 0.0735 0.0555 0.0825 0.0645 ;
    LAYER M2 ;
      RECT 0.118 0.0235 0.74 0.0325 ;
      RECT 0.066 0.0555 0.714 0.0645 ;
  END
END gtA5_cfet_5t_32_dffasync_x1_svt

MACRO gtA5_cfet_5t_32_dffpos_x1_svt
  CLASS CORE ;
  ORIGIN 0 0 ;
  FOREIGN gtA5_cfet_5t_32_dffpos_x1_svt 0 0 ;
  SIZE 0.858 BY 0.088 ;
  SYMMETRY X Y ;
  SITE CORESITE_5t_32 ;
  PIN VDD
    DIRECTION INOUT ;
    USE POWER ;
    SHAPE ABUTMENT ;
    PORT
      LAYER BPR ;
        RECT -0.0225 0.076 0.8805 0.1 ;
      LAYER VBPR ;
        RECT 0.0135 0.076 0.0255 0.086 ;
        RECT 0.0915 0.076 0.1035 0.086 ;
        RECT 0.1695 0.076 0.1815 0.086 ;
        RECT 0.2085 0.076 0.2205 0.086 ;
        RECT 0.2865 0.076 0.2985 0.086 ;
        RECT 0.3255 0.076 0.3375 0.086 ;
        RECT 0.4035 0.076 0.4155 0.086 ;
        RECT 0.4815 0.076 0.4935 0.086 ;
        RECT 0.5205 0.076 0.5325 0.086 ;
        RECT 0.5985 0.076 0.6105 0.086 ;
        RECT 0.6765 0.076 0.6885 0.086 ;
        RECT 0.7545 0.076 0.7665 0.086 ;
        RECT 0.8325 0.076 0.8445 0.086 ;
    END
  END VDD
  PIN VSS
    DIRECTION INOUT ;
    USE GROUND ;
    SHAPE ABUTMENT ;
    PORT
      LAYER BPR ;
        RECT -0.0225 -0.012 0.8805 0.012 ;
    END
  END VSS
  PIN CLK
    DIRECTION INPUT ;
    USE CLOCK ;
    PORT
      LAYER M1 ;
        RECT 0.59 0.0515 0.606 0.0845 ;
      LAYER M0 ;
        RECT 0.5895 0.0715 0.6325 0.0805 ;
        RECT 0.2295 0.0555 0.6065 0.0645 ;
      LAYER V0 ;
        RECT 0.5935 0.0715 0.6025 0.0805 ;
        RECT 0.5935 0.0555 0.6025 0.0645 ;
    END
  END CLK
  PIN D
    DIRECTION INPUT ;
    USE SIGNAL ;
    PORT
      LAYER M0 ;
        RECT 0.728 0.0235 0.776 0.0325 ;
    END
  END D
  PIN Q
    DIRECTION OUTPUT ;
    USE SIGNAL ;
    PORT
      LAYER M0 ;
        RECT 0.014 0.0075 0.1215 0.0165 ;
      LAYER VSD ;
        RECT 0.054 0.0075 0.063 0.0165 ;
    END
  END Q
  OBS
    LAYER VSD ;
      RECT 0.795 0.0075 0.804 0.0165 ;
      RECT 0.717 0.0075 0.726 0.0165 ;
      RECT 0.561 0.0715 0.57 0.0805 ;
      RECT 0.444 0.0075 0.453 0.0165 ;
      RECT 0.366 0.0075 0.375 0.0165 ;
      RECT 0.249 0.0715 0.258 0.0805 ;
      RECT 0.132 0.0715 0.141 0.0805 ;
    LAYER M0 ;
      RECT 0.794 0.0075 0.843 0.0165 ;
      RECT 0.6935 0.0715 0.8235 0.0805 ;
      RECT 0.69 0.0395 0.818 0.0485 ;
      RECT 0.5805 0.0075 0.7845 0.0165 ;
      RECT 0.6195 0.0555 0.7365 0.0645 ;
      RECT 0.4635 0.0235 0.714 0.0325 ;
      RECT 0.2685 0.0715 0.57 0.0805 ;
      RECT 0.444 0.0075 0.5505 0.0165 ;
      RECT 0.496 0.0395 0.544 0.0485 ;
      RECT 0.0735 0.0235 0.3945 0.0325 ;
      RECT 0.1515 0.0075 0.375 0.0165 ;
      RECT 0.213 0.0715 0.261 0.0805 ;
      RECT 0.118 0.0395 0.18 0.0485 ;
      RECT 0.0345 0.0715 0.142 0.0805 ;
    LAYER V0 ;
      RECT 0.8015 0.0075 0.8105 0.0165 ;
      RECT 0.8015 0.0395 0.8105 0.0485 ;
      RECT 0.7235 0.0555 0.7325 0.0645 ;
      RECT 0.7235 0.0715 0.7325 0.0805 ;
      RECT 0.6975 0.0235 0.7065 0.0325 ;
      RECT 0.6975 0.0395 0.7065 0.0485 ;
      RECT 0.5155 0.0395 0.5245 0.0485 ;
      RECT 0.5155 0.0715 0.5245 0.0805 ;
      RECT 0.2295 0.0235 0.2385 0.0325 ;
      RECT 0.2295 0.0715 0.2385 0.0805 ;
      RECT 0.1255 0.0395 0.1345 0.0485 ;
      RECT 0.1255 0.0715 0.1345 0.0805 ;
    LAYER M1 ;
      RECT 0.798 0.004 0.814 0.056 ;
      RECT 0.72 0.0515 0.736 0.0845 ;
      RECT 0.694 0.02 0.71 0.056 ;
      RECT 0.512 0.036 0.528 0.084 ;
      RECT 0.226 0.02 0.242 0.084 ;
      RECT 0.122 0.036 0.138 0.084 ;
  END
END gtA5_cfet_5t_32_dffpos_x1_svt


MACRO gtA5_cfet_5t_32_dffsyn_x1_svt
  CLASS CORE ;
  ORIGIN 0 0 ;
  FOREIGN gtA5_cfet_5t_32_dffsyn_x1_svt 0 0 ;
  SIZE 0.858 BY 0.088 ;
  SYMMETRY X Y ;
  SITE CORESITE_5t_32 ;
  PIN VDD
    DIRECTION INOUT ;
    USE POWER ;
    SHAPE ABUTMENT ;
    PORT
      LAYER BPR ;
        RECT -0.0225 0.076 0.8805 0.1 ;
      LAYER VBPR ;
        RECT 0.0135 0.076 0.0255 0.086 ;
        RECT 0.0915 0.076 0.1035 0.086 ;
        RECT 0.1695 0.076 0.1815 0.086 ;
        RECT 0.2085 0.076 0.2205 0.086 ;
        RECT 0.2865 0.076 0.2985 0.086 ;
        RECT 0.3255 0.076 0.3375 0.086 ;
        RECT 0.4035 0.076 0.4155 0.086 ;
        RECT 0.4815 0.076 0.4935 0.086 ;
        RECT 0.5205 0.076 0.5325 0.086 ;
        RECT 0.5985 0.076 0.6105 0.086 ;
        RECT 0.6765 0.076 0.6885 0.086 ;
        RECT 0.7545 0.076 0.7665 0.086 ;
        RECT 0.8325 0.076 0.8445 0.086 ;
    END
  END VDD
  PIN VSS
    DIRECTION INOUT ;
    USE GROUND ;
    SHAPE ABUTMENT ;
    PORT
      LAYER BPR ;
        RECT -0.0225 -0.012 0.8805 0.012 ;
    END
  END VSS
  PIN CLK
    DIRECTION INPUT ;
    USE CLOCK ;
    PORT
      LAYER M0 ;
        RECT 0.6195 0.0715 0.8235 0.0805 ;
    END
  END CLK
  PIN D
    DIRECTION INPUT ;
    USE SIGNAL ;
    PORT
      LAYER M0 ;
        RECT 0.728 0.0235 0.776 0.0325 ;
    END
  END D
  PIN Q
    DIRECTION OUTPUT ;
    USE SIGNAL ;
    PORT
      LAYER M0 ;
        RECT 0.014 0.0075 0.1215 0.0165 ;
      LAYER VSD ;
        RECT 0.054 0.0075 0.063 0.0165 ;
    END
  END Q
  OBS
    LAYER VSD ;
      RECT 0.795 0.0075 0.804 0.0165 ;
      RECT 0.717 0.0075 0.726 0.0165 ;
      RECT 0.561 0.0715 0.57 0.0805 ;
      RECT 0.444 0.0075 0.453 0.0165 ;
      RECT 0.366 0.0075 0.375 0.0165 ;
      RECT 0.249 0.0715 0.258 0.0805 ;
      RECT 0.132 0.0715 0.141 0.0805 ;
    LAYER M0 ;
      RECT 0.794 0.0075 0.843 0.0165 ;
      RECT 0.69 0.0395 0.818 0.0485 ;
      RECT 0.5805 0.0075 0.7845 0.0165 ;
      RECT 0.4635 0.0235 0.714 0.0325 ;
      RECT 0.2295 0.0555 0.648 0.0645 ;
      RECT 0.2685 0.0715 0.57 0.0805 ;
      RECT 0.444 0.0075 0.5505 0.0165 ;
      RECT 0.496 0.0395 0.544 0.0485 ;
      RECT 0.0735 0.0235 0.3945 0.0325 ;
      RECT 0.1515 0.0075 0.375 0.0165 ;
      RECT 0.213 0.0715 0.261 0.0805 ;
      RECT 0.118 0.0395 0.18 0.0485 ;
      RECT 0.0345 0.0715 0.142 0.0805 ;
    LAYER V0 ;
      RECT 0.8015 0.0075 0.8105 0.0165 ;
      RECT 0.8015 0.0395 0.8105 0.0485 ;
      RECT 0.6975 0.0235 0.7065 0.0325 ;
      RECT 0.6975 0.0395 0.7065 0.0485 ;
      RECT 0.5155 0.0395 0.5245 0.0485 ;
      RECT 0.5155 0.0715 0.5245 0.0805 ;
      RECT 0.2295 0.0235 0.2385 0.0325 ;
      RECT 0.2295 0.0715 0.2385 0.0805 ;
      RECT 0.1255 0.0395 0.1345 0.0485 ;
      RECT 0.1255 0.0715 0.1345 0.0805 ;
    LAYER M1 ;
      RECT 0.798 0.004 0.814 0.056 ;
      RECT 0.694 0.02 0.71 0.056 ;
      RECT 0.512 0.036 0.528 0.084 ;
      RECT 0.226 0.02 0.242 0.084 ;
      RECT 0.122 0.036 0.138 0.084 ;
  END
END gtA5_cfet_5t_32_dffsyn_x1_svt

MACRO gtA5_cfet_5t_32_dlatch_x1_svt
  CLASS CORE ;
  ORIGIN 0 0 ;
  FOREIGN gtA5_cfet_5t_32_dlatch_x1_svt 0 0 ;
  SIZE 0.39 BY 0.088 ;
  SYMMETRY X Y ;
  SITE CORESITE_5t_32 ;
  PIN VDD
    DIRECTION INOUT ;
    USE POWER ;
    SHAPE ABUTMENT ;
    PORT
      LAYER BPR ;
        RECT -0.0225 0.076 0.4125 0.1 ;
      LAYER VBPR ;
        RECT 0.0135 0.076 0.0255 0.086 ;
        RECT 0.0915 0.076 0.1035 0.086 ;
        RECT 0.1695 0.076 0.1815 0.086 ;
        RECT 0.2085 0.076 0.2205 0.086 ;
        RECT 0.2865 0.076 0.2985 0.086 ;
        RECT 0.3645 0.076 0.3765 0.086 ;
    END
  END VDD
  PIN VSS
    DIRECTION INOUT ;
    USE GROUND ;
    SHAPE ABUTMENT ;
    PORT
      LAYER BPR ;
        RECT -0.0225 -0.012 0.4125 0.012 ;
    END
  END VSS
  PIN Q
    DIRECTION OUTPUT ;
    USE SIGNAL ;
    PORT
      LAYER M0 ;
        RECT 0.014 0.0075 0.1215 0.0165 ;
      LAYER VSD ;
        RECT 0.054 0.0075 0.063 0.0165 ;
    END
  END Q
  PIN CLK
    DIRECTION INPUT ;
    USE CLOCK ;
    PORT
      LAYER M1 ;
        RECT 0.356 0.032 0.372 0.068 ;
        RECT 0.252 0.032 0.268 0.068 ;
      LAYER M0 ;
        RECT 0.334 0.0555 0.382 0.0645 ;
        RECT 0.248 0.0395 0.376 0.0485 ;
        RECT 0.226 0.0555 0.274 0.0645 ;
      LAYER V0 ;
        RECT 0.2555 0.0555 0.2645 0.0645 ;
        RECT 0.2555 0.0395 0.2645 0.0485 ;
        RECT 0.3595 0.0555 0.3685 0.0645 ;
        RECT 0.3595 0.0395 0.3685 0.0485 ;
    END
  END CLK
  PIN D
    DIRECTION INPUT ;
    USE SIGNAL ;
    PORT
      LAYER M1 ;
        RECT 0.304 0.043 0.32 0.068 ;
      LAYER M0 ;
        RECT 0.2795 0.0555 0.3275 0.0645 ;
      LAYER V0 ;
        RECT 0.3075 0.0555 0.3165 0.0645 ;
    END
  END D
  OBS
    LAYER VSD ;
      RECT 0.327 0.0075 0.336 0.0165 ;
      RECT 0.249 0.0075 0.258 0.0165 ;
      RECT 0.132 0.0715 0.141 0.0805 ;
    LAYER M0 ;
      RECT 0.2685 0.0075 0.375 0.0165 ;
      RECT 0.196 0.0235 0.298 0.0325 ;
      RECT 0.1515 0.0075 0.258 0.0165 ;
      RECT 0.0735 0.0555 0.22 0.0645 ;
      RECT 0.118 0.0395 0.18 0.0485 ;
      RECT 0.0345 0.0715 0.142 0.0805 ;
    LAYER V0 ;
      RECT 0.2815 0.0075 0.2905 0.0165 ;
      RECT 0.2815 0.0235 0.2905 0.0325 ;
      RECT 0.2035 0.0235 0.2125 0.0325 ;
      RECT 0.2035 0.0555 0.2125 0.0645 ;
      RECT 0.1255 0.0395 0.1345 0.0485 ;
      RECT 0.1255 0.0715 0.1345 0.0805 ;
    LAYER M1 ;
      RECT 0.278 0.004 0.294 0.04 ;
      RECT 0.2 0.016 0.216 0.068 ;
      RECT 0.122 0.036 0.138 0.084 ;
  END
END gtA5_cfet_5t_32_dlatch_x1_svt

MACRO gtA5_cfet_5t_32_ha_x1_svt
  CLASS CORE ;
  ORIGIN 0 0 ;
  FOREIGN gtA5_cfet_5t_32_ha_x1_svt 0 0 ;
  SIZE 0.273 BY 0.088 ;
  SYMMETRY X Y ;
  SITE CORESITE_5t_32 ;
  PIN VDD
    DIRECTION INOUT ;
    USE POWER ;
    SHAPE ABUTMENT ;
    PORT
      LAYER BPR ;
        RECT -0.0225 0.076 0.2955 0.1 ;
      LAYER VBPR ;
        RECT 0.0525 0.076 0.0645 0.086 ;
        RECT 0.1695 0.076 0.1815 0.086 ;
        RECT 0.2475 0.076 0.2595 0.086 ;
    END
  END VDD
  PIN VSS
    DIRECTION INOUT ;
    USE GROUND ;
    SHAPE ABUTMENT ;
    PORT
      LAYER BPR ;
        RECT -0.0225 -0.012 0.2955 0.012 ;
    END
  END VSS
  PIN A
    DIRECTION INPUT ;
    USE SIGNAL ;
    PORT
      LAYER M0 ;
        RECT 0.1125 0.0715 0.2385 0.0805 ;
    END
  END A
  PIN B
    DIRECTION INPUT ;
    USE SIGNAL ;
    PORT
      LAYER M0 ;
        RECT 0.1515 0.0555 0.1995 0.0645 ;
    END
  END B
  PIN CON
    DIRECTION OUTPUT ;
    USE SIGNAL ;
    PORT
      LAYER M0 ;
        RECT 0.0345 0.0075 0.219 0.0165 ;
      LAYER VSD ;
        RECT 0.21 0.0075 0.219 0.0165 ;
    END
  END CON
  PIN SN
    DIRECTION OUTPUT ;
    USE SIGNAL ;
    PORT
      LAYER M0 ;
        RECT 0.014 0.0715 0.102 0.0805 ;
      LAYER VSD ;
        RECT 0.093 0.0715 0.102 0.0805 ;
    END
  END SN
  OBS
    LAYER M0 ;
      RECT 0.054 0.0395 0.219 0.0485 ;
  END
END gtA5_cfet_5t_32_ha_x1_svt

MACRO gtA5_cfet_5t_32_inv_x10_svt
  CLASS CORE ;
  ORIGIN 0 0 ;
  FOREIGN gtA5_cfet_5t_32_inv_x10_svt 0 0 ;
  SIZE 0.429 BY 0.088 ;
  SYMMETRY X Y ;
  SITE CORESITE_5t_32 ;
  PIN VDD
    DIRECTION INOUT ;
    USE POWER ;
    SHAPE ABUTMENT ;
    PORT
      LAYER BPR ;
        RECT -0.0225 0.076 0.4515 0.1 ;
      LAYER VBPR ;
        RECT 0.0135 0.076 0.0255 0.086 ;
        RECT 0.0915 0.076 0.1035 0.086 ;
        RECT 0.1695 0.076 0.1815 0.086 ;
        RECT 0.2475 0.076 0.2595 0.086 ;
        RECT 0.3255 0.076 0.3375 0.086 ;
        RECT 0.4035 0.076 0.4155 0.086 ;
    END
  END VDD
  PIN VSS
    DIRECTION INOUT ;
    USE GROUND ;
    SHAPE ABUTMENT ;
    PORT
      LAYER BPR ;
        RECT -0.0225 -0.012 0.4515 0.012 ;
    END
  END VSS
  PIN A
    DIRECTION INPUT ;
    USE SIGNAL ;
    PORT
      LAYER M0 ;
        RECT 0.0345 0.0235 0.3945 0.0325 ;
    END
  END A
  PIN Y
    DIRECTION OUTPUT ;
    USE SIGNAL ;
    PORT
      LAYER M0 ;
        RECT 0.054 0.0075 0.375 0.0165 ;
      LAYER VSD ;
        RECT 0.054 0.0075 0.063 0.0165 ;
        RECT 0.132 0.0075 0.141 0.0165 ;
        RECT 0.21 0.0075 0.219 0.0165 ;
        RECT 0.288 0.0075 0.297 0.0165 ;
        RECT 0.366 0.0075 0.375 0.0165 ;
    END
  END Y
END gtA5_cfet_5t_32_inv_x10_svt

MACRO gtA5_cfet_5t_32_inv_x12_svt
  CLASS CORE ;
  ORIGIN 0 0 ;
  FOREIGN gtA5_cfet_5t_32_inv_x12_svt 0 0 ;
  SIZE 0.507 BY 0.088 ;
  SYMMETRY X Y ;
  SITE CORESITE_5t_32 ;
  PIN VDD
    DIRECTION INOUT ;
    USE POWER ;
    SHAPE ABUTMENT ;
    PORT
      LAYER BPR ;
        RECT -0.0225 0.076 0.5295 0.1 ;
      LAYER VBPR ;
        RECT 0.0135 0.076 0.0255 0.086 ;
        RECT 0.0915 0.076 0.1035 0.086 ;
        RECT 0.1695 0.076 0.1815 0.086 ;
        RECT 0.2475 0.076 0.2595 0.086 ;
        RECT 0.3255 0.076 0.3375 0.086 ;
        RECT 0.4035 0.076 0.4155 0.086 ;
        RECT 0.4815 0.076 0.4935 0.086 ;
    END
  END VDD
  PIN VSS
    DIRECTION INOUT ;
    USE GROUND ;
    SHAPE ABUTMENT ;
    PORT
      LAYER BPR ;
        RECT -0.0225 -0.012 0.5295 0.012 ;
    END
  END VSS
  PIN A
    DIRECTION INPUT ;
    USE SIGNAL ;
    PORT
      LAYER M0 ;
        RECT 0.0345 0.0235 0.4725 0.0325 ;
    END
  END A
  PIN Y
    DIRECTION OUTPUT ;
    USE SIGNAL ;
    PORT
      LAYER M0 ;
        RECT 0.054 0.0075 0.453 0.0165 ;
      LAYER VSD ;
        RECT 0.054 0.0075 0.063 0.0165 ;
        RECT 0.132 0.0075 0.141 0.0165 ;
        RECT 0.21 0.0075 0.219 0.0165 ;
        RECT 0.288 0.0075 0.297 0.0165 ;
        RECT 0.366 0.0075 0.375 0.0165 ;
        RECT 0.444 0.0075 0.453 0.0165 ;
    END
  END Y
END gtA5_cfet_5t_32_inv_x12_svt

MACRO gtA5_cfet_5t_32_inv_x1_svt
  CLASS CORE ;
  ORIGIN 0 0 ;
  FOREIGN gtA5_cfet_5t_32_inv_x1_svt 0 0 ;
  SIZE 0.078 BY 0.088 ;
  SYMMETRY X Y ;
  SITE CORESITE_5t_32 ;
  PIN VDD
    DIRECTION INOUT ;
    USE POWER ;
    SHAPE ABUTMENT ;
    PORT
      LAYER BPR ;
        RECT -0.0225 0.076 0.1005 0.1 ;
      LAYER VBPR ;
        RECT 0.0525 0.076 0.0645 0.086 ;
    END
  END VDD
  PIN VSS
    DIRECTION INOUT ;
    USE GROUND ;
    SHAPE ABUTMENT ;
    PORT
      LAYER BPR ;
        RECT -0.0225 -0.012 0.1005 0.012 ;
    END
  END VSS
  PIN A
    DIRECTION INPUT ;
    USE SIGNAL ;
    PORT
      LAYER M0 ;
        RECT 0.0095 0.0235 0.0575 0.0325 ;
    END
  END A
  PIN Y
    DIRECTION OUTPUT ;
    USE SIGNAL ;
    PORT
      LAYER M0 ;
        RECT 0.0095 0.0715 0.0575 0.0805 ;
    END
  END Y
END gtA5_cfet_5t_32_inv_x1_svt

MACRO gtA5_cfet_5t_32_inv_x2_svt
  CLASS CORE ;
  ORIGIN 0 0 ;
  FOREIGN gtA5_cfet_5t_32_inv_x2_svt 0 0 ;
  SIZE 0.117 BY 0.088 ;
  SYMMETRY X Y ;
  SITE CORESITE_5t_32 ;
  PIN VDD
    DIRECTION INOUT ;
    USE POWER ;
    SHAPE ABUTMENT ;
    PORT
      LAYER BPR ;
        RECT -0.0225 0.076 0.1395 0.1 ;
      LAYER VBPR ;
        RECT 0.0525 0.076 0.0645 0.086 ;
    END
  END VDD
  PIN VSS
    DIRECTION INOUT ;
    USE GROUND ;
    SHAPE ABUTMENT ;
    PORT
      LAYER BPR ;
        RECT -0.0225 -0.012 0.1395 0.012 ;
    END
  END VSS
  PIN A
    DIRECTION INPUT ;
    USE SIGNAL ;
    PORT
      LAYER M0 ;
        RECT 0.014 0.0555 0.0825 0.0645 ;
    END
  END A
  PIN Y
    DIRECTION OUTPUT ;
    USE SIGNAL ;
    PORT
      LAYER M0 ;
        RECT 0.015 0.0075 0.102 0.0165 ;
      LAYER VSD ;
        RECT 0.015 0.0075 0.024 0.0165 ;
        RECT 0.093 0.0075 0.102 0.0165 ;
    END
  END Y
END gtA5_cfet_5t_32_inv_x2_svt

MACRO gtA5_cfet_5t_32_inv_x3_svt
  CLASS CORE ;
  ORIGIN 0 0 ;
  FOREIGN gtA5_cfet_5t_32_inv_x3_svt 0 0 ;
  SIZE 0.156 BY 0.088 ;
  SYMMETRY X Y ;
  SITE CORESITE_5t_32 ;
  PIN VDD
    DIRECTION INOUT ;
    USE POWER ;
    SHAPE ABUTMENT ;
    PORT
      LAYER BPR ;
        RECT -0.0225 0.076 0.1785 0.1 ;
      LAYER VBPR ;
        RECT 0.0525 0.076 0.0645 0.086 ;
        RECT 0.1305 0.076 0.1425 0.086 ;
    END
  END VDD
  PIN VSS
    DIRECTION INOUT ;
    USE GROUND ;
    SHAPE ABUTMENT ;
    PORT
      LAYER BPR ;
        RECT -0.0225 -0.012 0.1785 0.012 ;
    END
  END VSS
  PIN A
    DIRECTION INPUT ;
    USE SIGNAL ;
    PORT
      LAYER M0 ;
        RECT 0.014 0.0555 0.1215 0.0645 ;
    END
  END A
  PIN Y
    DIRECTION OUTPUT ;
    USE SIGNAL ;
    PORT
      LAYER M0 ;
        RECT 0.015 0.0075 0.142 0.0165 ;
      LAYER VSD ;
        RECT 0.015 0.0075 0.024 0.0165 ;
        RECT 0.093 0.0075 0.102 0.0165 ;
    END
  END Y
END gtA5_cfet_5t_32_inv_x3_svt

MACRO gtA5_cfet_5t_32_inv_x4_svt
  CLASS CORE ;
  ORIGIN 0 0 ;
  FOREIGN gtA5_cfet_5t_32_inv_x4_svt 0 0 ;
  SIZE 0.195 BY 0.088 ;
  SYMMETRY X Y ;
  SITE CORESITE_5t_32 ;
  PIN VDD
    DIRECTION INOUT ;
    USE POWER ;
    SHAPE ABUTMENT ;
    PORT
      LAYER BPR ;
        RECT -0.0225 0.076 0.2175 0.1 ;
      LAYER VBPR ;
        RECT 0.0525 0.076 0.0645 0.086 ;
        RECT 0.1305 0.076 0.1425 0.086 ;
    END
  END VDD
  PIN VSS
    DIRECTION INOUT ;
    USE GROUND ;
    SHAPE ABUTMENT ;
    PORT
      LAYER BPR ;
        RECT -0.0225 -0.012 0.2175 0.012 ;
    END
  END VSS
  PIN A
    DIRECTION INPUT ;
    USE SIGNAL ;
    PORT
      LAYER M0 ;
        RECT 0.014 0.0555 0.1605 0.0645 ;
    END
  END A
  PIN Y
    DIRECTION OUTPUT ;
    USE SIGNAL ;
    PORT
      LAYER M0 ;
        RECT 0.015 0.0075 0.18 0.0165 ;
      LAYER VSD ;
        RECT 0.015 0.0075 0.024 0.0165 ;
        RECT 0.093 0.0075 0.102 0.0165 ;
        RECT 0.171 0.0075 0.18 0.0165 ;
    END
  END Y
END gtA5_cfet_5t_32_inv_x4_svt

MACRO gtA5_cfet_5t_32_inv_x6_svt
  CLASS CORE ;
  ORIGIN 0 0 ;
  FOREIGN gtA5_cfet_5t_32_inv_x6_svt 0 0 ;
  SIZE 0.273 BY 0.088 ;
  SYMMETRY X Y ;
  SITE CORESITE_5t_32 ;
  PIN VDD
    DIRECTION INOUT ;
    USE POWER ;
    SHAPE ABUTMENT ;
    PORT
      LAYER BPR ;
        RECT -0.0225 0.076 0.2955 0.1 ;
      LAYER VBPR ;
        RECT 0.0135 0.076 0.0255 0.086 ;
        RECT 0.0915 0.076 0.1035 0.086 ;
        RECT 0.1695 0.076 0.1815 0.086 ;
        RECT 0.2475 0.076 0.2595 0.086 ;
    END
  END VDD
  PIN VSS
    DIRECTION INOUT ;
    USE GROUND ;
    SHAPE ABUTMENT ;
    PORT
      LAYER BPR ;
        RECT -0.0225 -0.012 0.2955 0.012 ;
    END
  END VSS
  PIN A
    DIRECTION INPUT ;
    USE SIGNAL ;
    PORT
      LAYER M0 ;
        RECT 0.0345 0.0235 0.2385 0.0325 ;
    END
  END A
  PIN Y
    DIRECTION OUTPUT ;
    USE SIGNAL ;
    PORT
      LAYER M0 ;
        RECT 0.054 0.0075 0.219 0.0165 ;
      LAYER VSD ;
        RECT 0.054 0.0075 0.063 0.0165 ;
        RECT 0.132 0.0075 0.141 0.0165 ;
        RECT 0.21 0.0075 0.219 0.0165 ;
    END
  END Y
END gtA5_cfet_5t_32_inv_x6_svt

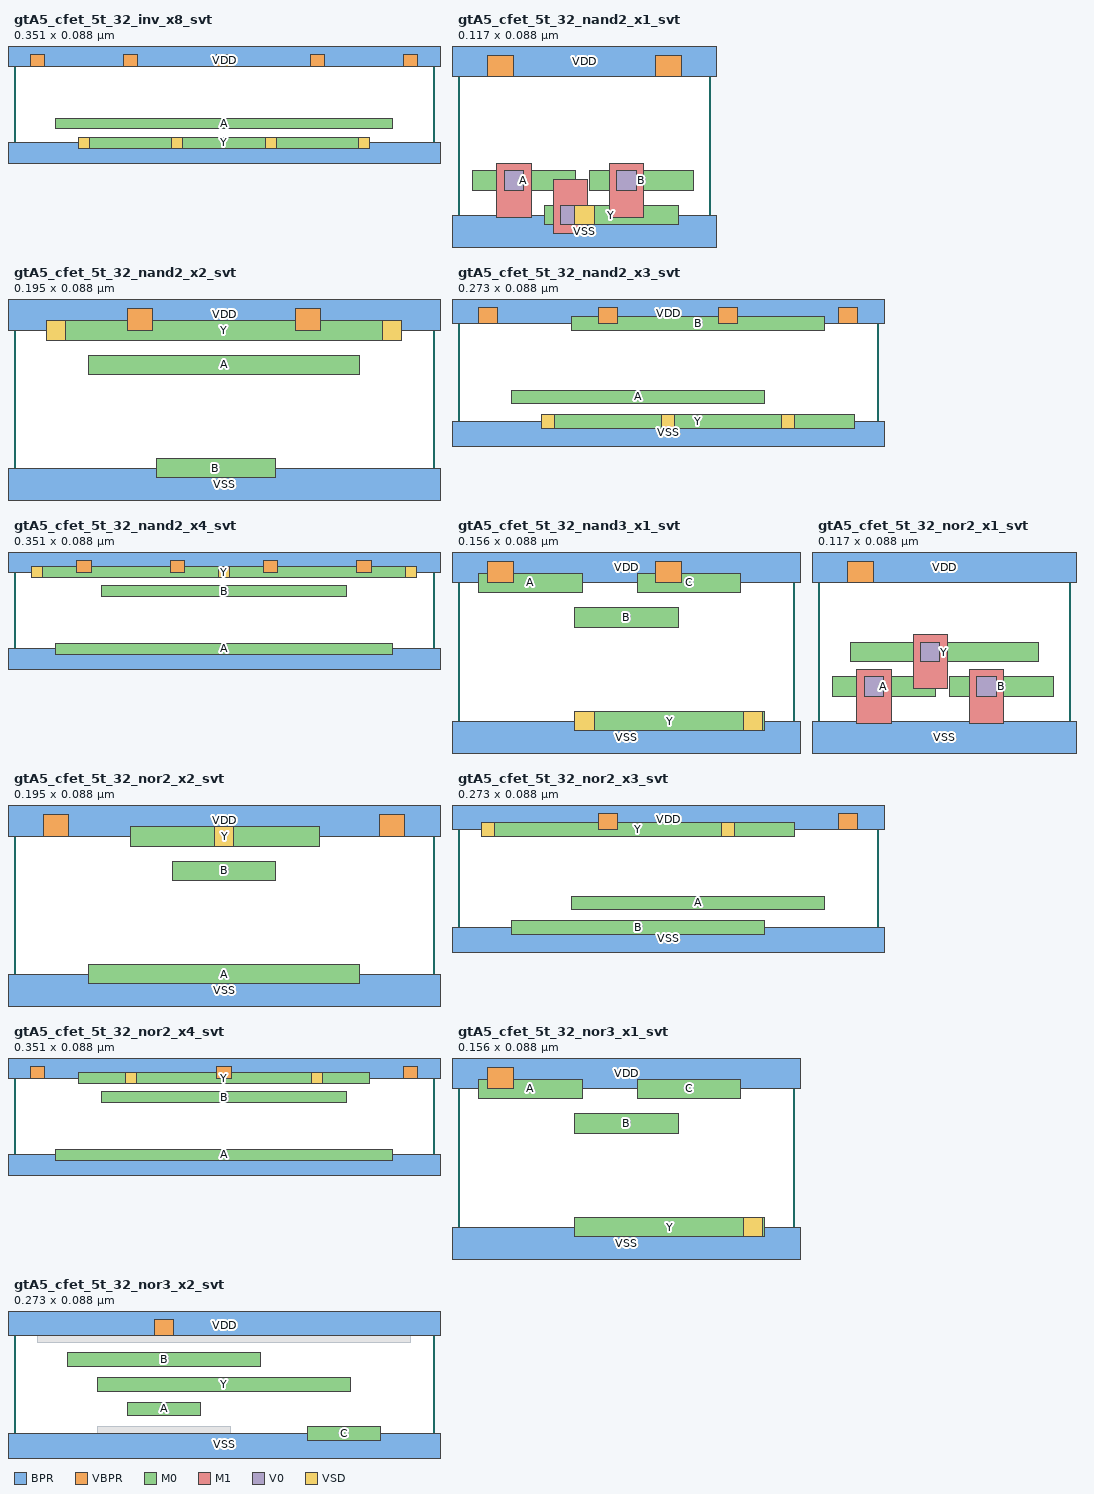
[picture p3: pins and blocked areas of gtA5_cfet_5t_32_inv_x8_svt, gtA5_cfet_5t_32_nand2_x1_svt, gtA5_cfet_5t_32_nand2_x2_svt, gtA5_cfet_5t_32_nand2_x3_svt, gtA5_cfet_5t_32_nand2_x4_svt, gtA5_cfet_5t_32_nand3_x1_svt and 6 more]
MACRO gtA5_cfet_5t_32_inv_x8_svt
  CLASS CORE ;
  ORIGIN 0 0 ;
  FOREIGN gtA5_cfet_5t_32_inv_x8_svt 0 0 ;
  SIZE 0.351 BY 0.088 ;
  SYMMETRY X Y ;
  SITE CORESITE_5t_32 ;
  PIN VDD
    DIRECTION INOUT ;
    USE POWER ;
    SHAPE ABUTMENT ;
    PORT
      LAYER BPR ;
        RECT -0.0225 0.076 0.3735 0.1 ;
      LAYER VBPR ;
        RECT 0.0135 0.076 0.0255 0.086 ;
        RECT 0.0915 0.076 0.1035 0.086 ;
        RECT 0.1695 0.076 0.1815 0.086 ;
        RECT 0.2475 0.076 0.2595 0.086 ;
        RECT 0.3255 0.076 0.3375 0.086 ;
    END
  END VDD
  PIN VSS
    DIRECTION INOUT ;
    USE GROUND ;
    SHAPE ABUTMENT ;
    PORT
      LAYER BPR ;
        RECT -0.0225 -0.012 0.3735 0.012 ;
    END
  END VSS
  PIN A
    DIRECTION INPUT ;
    USE SIGNAL ;
    PORT
      LAYER M0 ;
        RECT 0.0345 0.0235 0.3165 0.0325 ;
    END
  END A
  PIN Y
    DIRECTION OUTPUT ;
    USE SIGNAL ;
    PORT
      LAYER M0 ;
        RECT 0.054 0.0075 0.297 0.0165 ;
      LAYER VSD ;
        RECT 0.054 0.0075 0.063 0.0165 ;
        RECT 0.132 0.0075 0.141 0.0165 ;
        RECT 0.21 0.0075 0.219 0.0165 ;
        RECT 0.288 0.0075 0.297 0.0165 ;
    END
  END Y
END gtA5_cfet_5t_32_inv_x8_svt

MACRO gtA5_cfet_5t_32_nand2_x1_svt
  CLASS CORE ;
  ORIGIN 0 0 ;
  FOREIGN gtA5_cfet_5t_32_nand2_x1_svt 0 0 ;
  SIZE 0.117 BY 0.088 ;
  SYMMETRY X Y ;
  SITE CORESITE_5t_32 ;
  PIN VDD
    DIRECTION INOUT ;
    USE POWER ;
    SHAPE ABUTMENT ;
    PORT
      LAYER BPR ;
        RECT -0.0225 0.076 0.1395 0.1 ;
      LAYER VBPR ;
        RECT 0.0135 0.076 0.0255 0.086 ;
        RECT 0.0915 0.076 0.1035 0.086 ;
    END
  END VDD
  PIN VSS
    DIRECTION INOUT ;
    USE GROUND ;
    SHAPE ABUTMENT ;
    PORT
      LAYER BPR ;
        RECT -0.0225 -0.012 0.1395 0.012 ;
    END
  END VSS
  PIN A
    DIRECTION INPUT ;
    USE SIGNAL ;
    PORT
      LAYER M0 ;
        RECT 0.0065 0.0235 0.0545 0.0325 ;
      LAYER M1 ;
        RECT 0.018 0.011 0.034 0.036 ;
      LAYER V0 ;
        RECT 0.0215 0.0235 0.0305 0.0325 ;
    END
  END A
  PIN B
    DIRECTION INPUT ;
    USE SIGNAL ;
    PORT
      LAYER M0 ;
        RECT 0.061 0.0235 0.109 0.0325 ;
      LAYER M1 ;
        RECT 0.07 0.011 0.086 0.036 ;
      LAYER V0 ;
        RECT 0.0735 0.0235 0.0825 0.0325 ;
    END
  END B
  PIN Y
    DIRECTION OUTPUT ;
    USE SIGNAL ;
    PORT
      LAYER M0 ;
        RECT 0.04 0.0075 0.102 0.0165 ;
      LAYER M1 ;
        RECT 0.044 0.0035 0.06 0.0285 ;
      LAYER V0 ;
        RECT 0.0475 0.0075 0.0565 0.0165 ;
      LAYER VSD ;
        RECT 0.054 0.0075 0.063 0.0165 ;
    END
  END Y
END gtA5_cfet_5t_32_nand2_x1_svt

MACRO gtA5_cfet_5t_32_nand2_x2_svt
  CLASS CORE ;
  ORIGIN 0 0 ;
  FOREIGN gtA5_cfet_5t_32_nand2_x2_svt 0 0 ;
  SIZE 0.195 BY 0.088 ;
  SYMMETRY X Y ;
  SITE CORESITE_5t_32 ;
  PIN VDD
    DIRECTION INOUT ;
    USE POWER ;
    SHAPE ABUTMENT ;
    PORT
      LAYER BPR ;
        RECT -0.0225 0.076 0.2175 0.1 ;
      LAYER VBPR ;
        RECT 0.0525 0.076 0.0645 0.086 ;
        RECT 0.1305 0.076 0.1425 0.086 ;
    END
  END VDD
  PIN VSS
    DIRECTION INOUT ;
    USE GROUND ;
    SHAPE ABUTMENT ;
    PORT
      LAYER BPR ;
        RECT -0.0225 -0.012 0.2175 0.012 ;
    END
  END VSS
  PIN A
    DIRECTION INPUT ;
    USE SIGNAL ;
    PORT
      LAYER M0 ;
        RECT 0.0345 0.0555 0.1605 0.0645 ;
    END
  END A
  PIN B
    DIRECTION INPUT ;
    USE SIGNAL ;
    PORT
      LAYER M0 ;
        RECT 0.066 0.0075 0.1215 0.0165 ;
    END
  END B
  PIN Y
    DIRECTION OUTPUT ;
    USE SIGNAL ;
    PORT
      LAYER M0 ;
        RECT 0.015 0.0715 0.18 0.0805 ;
      LAYER VSD ;
        RECT 0.015 0.0715 0.024 0.0805 ;
        RECT 0.171 0.0715 0.18 0.0805 ;
    END
  END Y
END gtA5_cfet_5t_32_nand2_x2_svt

MACRO gtA5_cfet_5t_32_nand2_x3_svt
  CLASS CORE ;
  ORIGIN 0 0 ;
  FOREIGN gtA5_cfet_5t_32_nand2_x3_svt 0 0 ;
  SIZE 0.273 BY 0.088 ;
  SYMMETRY X Y ;
  SITE CORESITE_5t_32 ;
  PIN VDD
    DIRECTION INOUT ;
    USE POWER ;
    SHAPE ABUTMENT ;
    PORT
      LAYER BPR ;
        RECT -0.0225 0.076 0.2955 0.1 ;
      LAYER VBPR ;
        RECT 0.0135 0.076 0.0255 0.086 ;
        RECT 0.0915 0.076 0.1035 0.086 ;
        RECT 0.1695 0.076 0.1815 0.086 ;
        RECT 0.2475 0.076 0.2595 0.086 ;
    END
  END VDD
  PIN VSS
    DIRECTION INOUT ;
    USE GROUND ;
    SHAPE ABUTMENT ;
    PORT
      LAYER BPR ;
        RECT -0.0225 -0.012 0.2955 0.012 ;
    END
  END VSS
  PIN A
    DIRECTION INPUT ;
    USE SIGNAL ;
    PORT
      LAYER M0 ;
        RECT 0.0345 0.0235 0.1995 0.0325 ;
    END
  END A
  PIN B
    DIRECTION INPUT ;
    USE SIGNAL ;
    PORT
      LAYER M0 ;
        RECT 0.0735 0.0715 0.2385 0.0805 ;
    END
  END B
  PIN Y
    DIRECTION OUTPUT ;
    USE SIGNAL ;
    PORT
      LAYER M0 ;
        RECT 0.054 0.0075 0.258 0.0165 ;
      LAYER VSD ;
        RECT 0.054 0.0075 0.063 0.0165 ;
        RECT 0.132 0.0075 0.141 0.0165 ;
        RECT 0.21 0.0075 0.219 0.0165 ;
    END
  END Y
END gtA5_cfet_5t_32_nand2_x3_svt

MACRO gtA5_cfet_5t_32_nand2_x4_svt
  CLASS CORE ;
  ORIGIN 0 0 ;
  FOREIGN gtA5_cfet_5t_32_nand2_x4_svt 0 0 ;
  SIZE 0.351 BY 0.088 ;
  SYMMETRY X Y ;
  SITE CORESITE_5t_32 ;
  PIN VDD
    DIRECTION INOUT ;
    USE POWER ;
    SHAPE ABUTMENT ;
    PORT
      LAYER BPR ;
        RECT -0.0225 0.076 0.3735 0.1 ;
      LAYER VBPR ;
        RECT 0.0525 0.076 0.0645 0.086 ;
        RECT 0.1305 0.076 0.1425 0.086 ;
        RECT 0.2085 0.076 0.2205 0.086 ;
        RECT 0.2865 0.076 0.2985 0.086 ;
    END
  END VDD
  PIN VSS
    DIRECTION INOUT ;
    USE GROUND ;
    SHAPE ABUTMENT ;
    PORT
      LAYER BPR ;
        RECT -0.0225 -0.012 0.3735 0.012 ;
    END
  END VSS
  PIN A
    DIRECTION INPUT ;
    USE SIGNAL ;
    PORT
      LAYER M0 ;
        RECT 0.0345 0.0075 0.3165 0.0165 ;
    END
  END A
  PIN B
    DIRECTION INPUT ;
    USE SIGNAL ;
    PORT
      LAYER M0 ;
        RECT 0.0735 0.0555 0.2775 0.0645 ;
    END
  END B
  PIN Y
    DIRECTION OUTPUT ;
    USE SIGNAL ;
    PORT
      LAYER M0 ;
        RECT 0.015 0.0715 0.336 0.0805 ;
      LAYER VSD ;
        RECT 0.015 0.0715 0.024 0.0805 ;
        RECT 0.171 0.0715 0.18 0.0805 ;
        RECT 0.327 0.0715 0.336 0.0805 ;
    END
  END Y
END gtA5_cfet_5t_32_nand2_x4_svt

MACRO gtA5_cfet_5t_32_nand3_x1_svt
  CLASS CORE ;
  ORIGIN 0 0 ;
  FOREIGN gtA5_cfet_5t_32_nand3_x1_svt 0 0 ;
  SIZE 0.156 BY 0.088 ;
  SYMMETRY X Y ;
  SITE CORESITE_5t_32 ;
  PIN VDD
    DIRECTION INOUT ;
    USE POWER ;
    SHAPE ABUTMENT ;
    PORT
      LAYER BPR ;
        RECT -0.0225 0.076 0.1785 0.1 ;
      LAYER VBPR ;
        RECT 0.0135 0.076 0.0255 0.086 ;
        RECT 0.0915 0.076 0.1035 0.086 ;
    END
  END VDD
  PIN VSS
    DIRECTION INOUT ;
    USE GROUND ;
    SHAPE ABUTMENT ;
    PORT
      LAYER BPR ;
        RECT -0.0225 -0.012 0.1785 0.012 ;
    END
  END VSS
  PIN A
    DIRECTION INPUT ;
    USE SIGNAL ;
    PORT
      LAYER M0 ;
        RECT 0.0095 0.0715 0.0575 0.0805 ;
    END
  END A
  PIN B
    DIRECTION INPUT ;
    USE SIGNAL ;
    PORT
      LAYER M0 ;
        RECT 0.054 0.0555 0.102 0.0645 ;
    END
  END B
  PIN C
    DIRECTION INPUT ;
    USE SIGNAL ;
    PORT
      LAYER M0 ;
        RECT 0.083 0.0715 0.131 0.0805 ;
    END
  END C
  PIN Y
    DIRECTION OUTPUT ;
    USE SIGNAL ;
    PORT
      LAYER M0 ;
        RECT 0.054 0.0075 0.142 0.0165 ;
      LAYER VSD ;
        RECT 0.054 0.0075 0.063 0.0165 ;
        RECT 0.132 0.0075 0.141 0.0165 ;
    END
  END Y
END gtA5_cfet_5t_32_nand3_x1_svt

MACRO gtA5_cfet_5t_32_nor2_x1_svt
  CLASS CORE ;
  ORIGIN 0 0 ;
  FOREIGN gtA5_cfet_5t_32_nor2_x1_svt 0 0 ;
  SIZE 0.117 BY 0.088 ;
  SYMMETRY X Y ;
  SITE CORESITE_5t_32 ;
  PIN VDD
    DIRECTION INOUT ;
    USE POWER ;
    SHAPE ABUTMENT ;
    PORT
      LAYER BPR ;
        RECT -0.0225 0.076 0.1395 0.1 ;
      LAYER VBPR ;
        RECT 0.0135 0.076 0.0255 0.086 ;
    END
  END VDD
  PIN VSS
    DIRECTION INOUT ;
    USE GROUND ;
    SHAPE ABUTMENT ;
    PORT
      LAYER BPR ;
        RECT -0.0225 -0.012 0.1395 0.012 ;
    END
  END VSS
  PIN A
    DIRECTION INPUT ;
    USE SIGNAL ;
    PORT
      LAYER M0 ;
        RECT 0.0065 0.0235 0.0545 0.0325 ;
      LAYER M1 ;
        RECT 0.018 0.011 0.034 0.036 ;
      LAYER V0 ;
        RECT 0.0215 0.0235 0.0305 0.0325 ;
    END
  END A
  PIN B
    DIRECTION INPUT ;
    USE SIGNAL ;
    PORT
      LAYER M0 ;
        RECT 0.061 0.0235 0.109 0.0325 ;
      LAYER M1 ;
        RECT 0.07 0.011 0.086 0.036 ;
      LAYER V0 ;
        RECT 0.0735 0.0235 0.0825 0.0325 ;
    END
  END B
  PIN Y
    DIRECTION OUTPUT ;
    USE SIGNAL ;
    PORT
      LAYER M0 ;
        RECT 0.015 0.0395 0.102 0.0485 ;
      LAYER M1 ;
        RECT 0.044 0.027 0.06 0.052 ;
      LAYER V0 ;
        RECT 0.0475 0.0395 0.0565 0.0485 ;
    END
  END Y
END gtA5_cfet_5t_32_nor2_x1_svt

MACRO gtA5_cfet_5t_32_nor2_x2_svt
  CLASS CORE ;
  ORIGIN 0 0 ;
  FOREIGN gtA5_cfet_5t_32_nor2_x2_svt 0 0 ;
  SIZE 0.195 BY 0.088 ;
  SYMMETRY X Y ;
  SITE CORESITE_5t_32 ;
  PIN VDD
    DIRECTION INOUT ;
    USE POWER ;
    SHAPE ABUTMENT ;
    PORT
      LAYER BPR ;
        RECT -0.0225 0.076 0.2175 0.1 ;
      LAYER VBPR ;
        RECT 0.0135 0.076 0.0255 0.086 ;
        RECT 0.1695 0.076 0.1815 0.086 ;
    END
  END VDD
  PIN VSS
    DIRECTION INOUT ;
    USE GROUND ;
    SHAPE ABUTMENT ;
    PORT
      LAYER BPR ;
        RECT -0.0225 -0.012 0.2175 0.012 ;
    END
  END VSS
  PIN A
    DIRECTION INPUT ;
    USE SIGNAL ;
    PORT
      LAYER M0 ;
        RECT 0.0345 0.0075 0.1605 0.0165 ;
    END
  END A
  PIN B
    DIRECTION INPUT ;
    USE SIGNAL ;
    PORT
      LAYER M0 ;
        RECT 0.0735 0.0555 0.1215 0.0645 ;
    END
  END B
  PIN Y
    DIRECTION OUTPUT ;
    USE SIGNAL ;
    PORT
      LAYER M0 ;
        RECT 0.054 0.0715 0.142 0.0805 ;
      LAYER VSD ;
        RECT 0.093 0.0715 0.102 0.0805 ;
    END
  END Y
END gtA5_cfet_5t_32_nor2_x2_svt

MACRO gtA5_cfet_5t_32_nor2_x3_svt
  CLASS CORE ;
  ORIGIN 0 0 ;
  FOREIGN gtA5_cfet_5t_32_nor2_x3_svt 0 0 ;
  SIZE 0.273 BY 0.088 ;
  SYMMETRY X Y ;
  SITE CORESITE_5t_32 ;
  PIN VDD
    DIRECTION INOUT ;
    USE POWER ;
    SHAPE ABUTMENT ;
    PORT
      LAYER BPR ;
        RECT -0.0225 0.076 0.2955 0.1 ;
      LAYER VBPR ;
        RECT 0.0915 0.076 0.1035 0.086 ;
        RECT 0.2475 0.076 0.2595 0.086 ;
    END
  END VDD
  PIN VSS
    DIRECTION INOUT ;
    USE GROUND ;
    SHAPE ABUTMENT ;
    PORT
      LAYER BPR ;
        RECT -0.0225 -0.012 0.2955 0.012 ;
    END
  END VSS
  PIN A
    DIRECTION INPUT ;
    USE SIGNAL ;
    PORT
      LAYER M0 ;
        RECT 0.0735 0.0235 0.2385 0.0325 ;
    END
  END A
  PIN B
    DIRECTION INPUT ;
    USE SIGNAL ;
    PORT
      LAYER M0 ;
        RECT 0.0345 0.0075 0.1995 0.0165 ;
    END
  END B
  PIN Y
    DIRECTION OUTPUT ;
    USE SIGNAL ;
    PORT
      LAYER M0 ;
        RECT 0.015 0.0715 0.219 0.0805 ;
      LAYER VSD ;
        RECT 0.015 0.0715 0.024 0.0805 ;
        RECT 0.171 0.0715 0.18 0.0805 ;
    END
  END Y
END gtA5_cfet_5t_32_nor2_x3_svt

MACRO gtA5_cfet_5t_32_nor2_x4_svt
  CLASS CORE ;
  ORIGIN 0 0 ;
  FOREIGN gtA5_cfet_5t_32_nor2_x4_svt 0 0 ;
  SIZE 0.351 BY 0.088 ;
  SYMMETRY X Y ;
  SITE CORESITE_5t_32 ;
  PIN VDD
    DIRECTION INOUT ;
    USE POWER ;
    SHAPE ABUTMENT ;
    PORT
      LAYER BPR ;
        RECT -0.0225 0.076 0.3735 0.1 ;
      LAYER VBPR ;
        RECT 0.0135 0.076 0.0255 0.086 ;
        RECT 0.1695 0.076 0.1815 0.086 ;
        RECT 0.3255 0.076 0.3375 0.086 ;
    END
  END VDD
  PIN VSS
    DIRECTION INOUT ;
    USE GROUND ;
    SHAPE ABUTMENT ;
    PORT
      LAYER BPR ;
        RECT -0.0225 -0.012 0.3735 0.012 ;
    END
  END VSS
  PIN A
    DIRECTION INPUT ;
    USE SIGNAL ;
    PORT
      LAYER M0 ;
        RECT 0.0345 0.0075 0.3165 0.0165 ;
    END
  END A
  PIN B
    DIRECTION INPUT ;
    USE SIGNAL ;
    PORT
      LAYER M0 ;
        RECT 0.0735 0.0555 0.2775 0.0645 ;
    END
  END B
  PIN Y
    DIRECTION OUTPUT ;
    USE SIGNAL ;
    PORT
      LAYER M0 ;
        RECT 0.054 0.0715 0.297 0.0805 ;
      LAYER VSD ;
        RECT 0.093 0.0715 0.102 0.0805 ;
        RECT 0.249 0.0715 0.258 0.0805 ;
    END
  END Y
END gtA5_cfet_5t_32_nor2_x4_svt

MACRO gtA5_cfet_5t_32_nor3_x1_svt
  CLASS CORE ;
  ORIGIN 0 0 ;
  FOREIGN gtA5_cfet_5t_32_nor3_x1_svt 0 0 ;
  SIZE 0.156 BY 0.088 ;
  SYMMETRY X Y ;
  SITE CORESITE_5t_32 ;
  PIN VDD
    DIRECTION INOUT ;
    USE POWER ;
    SHAPE ABUTMENT ;
    PORT
      LAYER BPR ;
        RECT -0.0225 0.076 0.1785 0.1 ;
      LAYER VBPR ;
        RECT 0.0135 0.076 0.0255 0.086 ;
    END
  END VDD
  PIN VSS
    DIRECTION INOUT ;
    USE GROUND ;
    SHAPE ABUTMENT ;
    PORT
      LAYER BPR ;
        RECT -0.0225 -0.012 0.1785 0.012 ;
    END
  END VSS
  PIN A
    DIRECTION INPUT ;
    USE SIGNAL ;
    PORT
      LAYER M0 ;
        RECT 0.0095 0.0715 0.0575 0.0805 ;
    END
  END A
  PIN B
    DIRECTION INPUT ;
    USE SIGNAL ;
    PORT
      LAYER M0 ;
        RECT 0.054 0.0555 0.102 0.0645 ;
    END
  END B
  PIN C
    DIRECTION INPUT ;
    USE SIGNAL ;
    PORT
      LAYER M0 ;
        RECT 0.083 0.0715 0.131 0.0805 ;
    END
  END C
  PIN Y
    DIRECTION OUTPUT ;
    USE SIGNAL ;
    PORT
      LAYER M0 ;
        RECT 0.054 0.0075 0.142 0.0165 ;
      LAYER VSD ;
        RECT 0.132 0.0075 0.141 0.0165 ;
    END
  END Y
END gtA5_cfet_5t_32_nor3_x1_svt

MACRO gtA5_cfet_5t_32_nor3_x2_svt
  CLASS CORE ;
  ORIGIN 0 0 ;
  FOREIGN gtA5_cfet_5t_32_nor3_x2_svt 0 0 ;
  SIZE 0.273 BY 0.088 ;
  SYMMETRY X Y ;
  SITE CORESITE_5t_32 ;
  PIN VDD
    DIRECTION INOUT ;
    USE POWER ;
    SHAPE ABUTMENT ;
    PORT
      LAYER BPR ;
        RECT -0.0225 0.076 0.2955 0.1 ;
      LAYER VBPR ;
        RECT 0.0915 0.076 0.1035 0.086 ;
    END
  END VDD
  PIN VSS
    DIRECTION INOUT ;
    USE GROUND ;
    SHAPE ABUTMENT ;
    PORT
      LAYER BPR ;
        RECT -0.0225 -0.012 0.2955 0.012 ;
    END
  END VSS
  PIN A
    DIRECTION INPUT ;
    USE SIGNAL ;
    PORT
      LAYER M0 ;
        RECT 0.0735 0.0235 0.1215 0.0325 ;
    END
  END A
  PIN B
    DIRECTION INPUT ;
    USE SIGNAL ;
    PORT
      LAYER M0 ;
        RECT 0.0345 0.0555 0.1605 0.0645 ;
    END
  END B
  PIN C
    DIRECTION INPUT ;
    USE SIGNAL ;
    PORT
      LAYER M0 ;
        RECT 0.1905 0.0075 0.2385 0.0165 ;
    END
  END C
  PIN Y
    DIRECTION OUTPUT ;
    USE SIGNAL ;
    PORT
      LAYER M0 ;
        RECT 0.054 0.0395 0.219 0.0485 ;
    END
  END Y
  OBS
    LAYER VSD ;
      RECT 0.249 0.0715 0.258 0.0805 ;
      RECT 0.171 0.0715 0.18 0.0805 ;
      RECT 0.132 0.0075 0.141 0.0165 ;
      RECT 0.054 0.0075 0.063 0.0165 ;
      RECT 0.015 0.0715 0.024 0.0805 ;
    LAYER M0 ;
      RECT 0.015 0.0715 0.258 0.0805 ;
      RECT 0.054 0.0075 0.141 0.0165 ;
  END
END gtA5_cfet_5t_32_nor3_x2_svt

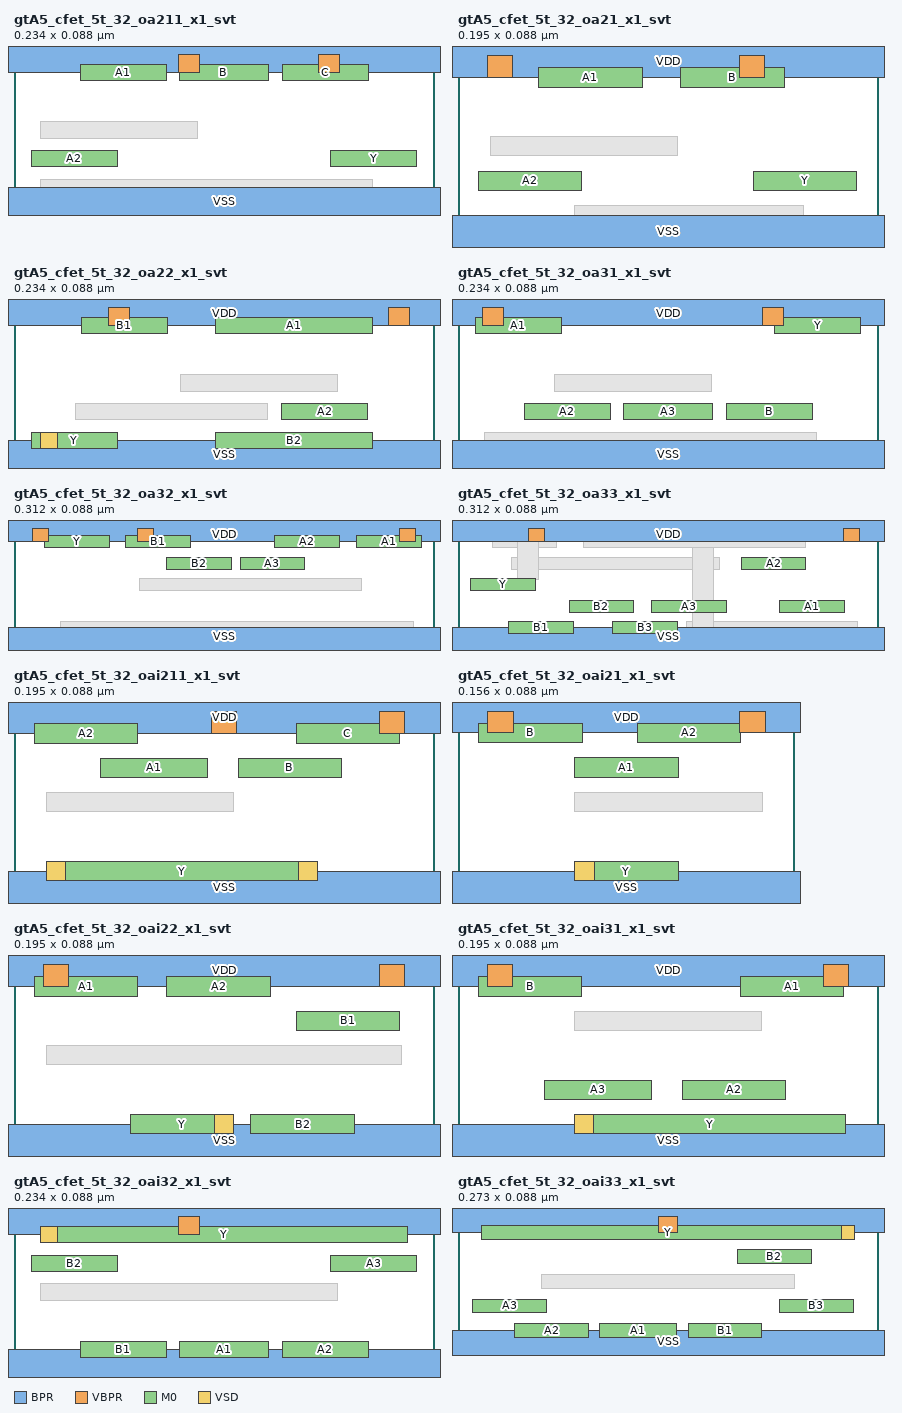
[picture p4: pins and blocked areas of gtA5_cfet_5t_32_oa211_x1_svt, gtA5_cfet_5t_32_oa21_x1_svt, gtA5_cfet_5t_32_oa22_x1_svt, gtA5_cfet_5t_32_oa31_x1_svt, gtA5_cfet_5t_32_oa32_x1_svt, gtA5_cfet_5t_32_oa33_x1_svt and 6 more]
MACRO gtA5_cfet_5t_32_oa211_x1_svt
  CLASS CORE ;
  ORIGIN 0 0 ;
  FOREIGN gtA5_cfet_5t_32_oa211_x1_svt 0 0 ;
  SIZE 0.234 BY 0.088 ;
  SYMMETRY X Y ;
  SITE CORESITE_5t_32 ;
  PIN VDD
    DIRECTION INOUT ;
    USE POWER ;
    SHAPE ABUTMENT ;
    PORT
      LAYER BPR ;
        RECT -0.0225 0.076 0.2565 0.1 ;
      LAYER VBPR ;
        RECT 0.0915 0.076 0.1035 0.086 ;
        RECT 0.1695 0.076 0.1815 0.086 ;
    END
  END VDD
  PIN VSS
    DIRECTION INOUT ;
    USE GROUND ;
    SHAPE ABUTMENT ;
    PORT
      LAYER BPR ;
        RECT -0.0225 -0.012 0.2565 0.012 ;
    END
  END VSS
  PIN A1
    DIRECTION INPUT ;
    USE SIGNAL ;
    PORT
      LAYER M0 ;
        RECT 0.037 0.0715 0.085 0.0805 ;
    END
  END A1
  PIN A2
    DIRECTION INPUT ;
    USE SIGNAL ;
    PORT
      LAYER M0 ;
        RECT 0.0095 0.0235 0.0575 0.0325 ;
    END
  END A2
  PIN B
    DIRECTION INPUT ;
    USE SIGNAL ;
    PORT
      LAYER M0 ;
        RECT 0.092 0.0715 0.142 0.0805 ;
    END
  END B
  PIN C
    DIRECTION INPUT ;
    USE SIGNAL ;
    PORT
      LAYER M0 ;
        RECT 0.1495 0.0715 0.1975 0.0805 ;
    END
  END C
  PIN Y
    DIRECTION OUTPUT ;
    USE SIGNAL ;
    PORT
      LAYER M0 ;
        RECT 0.1765 0.0235 0.2245 0.0325 ;
    END
  END Y
  OBS
    LAYER VSD ;
      RECT 0.132 0.0075 0.141 0.0165 ;
      RECT 0.015 0.0075 0.024 0.0165 ;
    LAYER M0 ;
      RECT 0.015 0.0075 0.1995 0.0165 ;
      RECT 0.015 0.0395 0.102 0.0485 ;
  END
END gtA5_cfet_5t_32_oa211_x1_svt

MACRO gtA5_cfet_5t_32_oa21_x1_svt
  CLASS CORE ;
  ORIGIN 0 0 ;
  FOREIGN gtA5_cfet_5t_32_oa21_x1_svt 0 0 ;
  SIZE 0.195 BY 0.088 ;
  SYMMETRY X Y ;
  SITE CORESITE_5t_32 ;
  PIN VDD
    DIRECTION INOUT ;
    USE POWER ;
    SHAPE ABUTMENT ;
    PORT
      LAYER BPR ;
        RECT -0.0225 0.076 0.2175 0.1 ;
      LAYER VBPR ;
        RECT 0.0135 0.076 0.0255 0.086 ;
        RECT 0.1305 0.076 0.1425 0.086 ;
    END
  END VDD
  PIN VSS
    DIRECTION INOUT ;
    USE GROUND ;
    SHAPE ABUTMENT ;
    PORT
      LAYER BPR ;
        RECT -0.0225 -0.012 0.2175 0.012 ;
    END
  END VSS
  PIN A1
    DIRECTION INPUT ;
    USE SIGNAL ;
    PORT
      LAYER M0 ;
        RECT 0.0375 0.0715 0.0855 0.0805 ;
    END
  END A1
  PIN A2
    DIRECTION INPUT ;
    USE SIGNAL ;
    PORT
      LAYER M0 ;
        RECT 0.0095 0.0235 0.0575 0.0325 ;
    END
  END A2
  PIN B
    DIRECTION INPUT ;
    USE SIGNAL ;
    PORT
      LAYER M0 ;
        RECT 0.1035 0.0715 0.1515 0.0805 ;
    END
  END B
  PIN Y
    DIRECTION OUTPUT ;
    USE SIGNAL ;
    PORT
      LAYER M0 ;
        RECT 0.137 0.0235 0.185 0.0325 ;
    END
  END Y
  OBS
    LAYER VSD ;
      RECT 0.093 0.0075 0.102 0.0165 ;
    LAYER M0 ;
      RECT 0.054 0.0075 0.1605 0.0165 ;
      RECT 0.015 0.0395 0.102 0.0485 ;
  END
END gtA5_cfet_5t_32_oa21_x1_svt

MACRO gtA5_cfet_5t_32_oa22_x1_svt
  CLASS CORE ;
  ORIGIN 0 0 ;
  FOREIGN gtA5_cfet_5t_32_oa22_x1_svt 0 0 ;
  SIZE 0.234 BY 0.088 ;
  SYMMETRY X Y ;
  SITE CORESITE_5t_32 ;
  PIN VDD
    DIRECTION INOUT ;
    USE POWER ;
    SHAPE ABUTMENT ;
    PORT
      LAYER BPR ;
        RECT -0.0225 0.076 0.2565 0.1 ;
      LAYER VBPR ;
        RECT 0.0525 0.076 0.0645 0.086 ;
        RECT 0.2085 0.076 0.2205 0.086 ;
    END
  END VDD
  PIN VSS
    DIRECTION INOUT ;
    USE GROUND ;
    SHAPE ABUTMENT ;
    PORT
      LAYER BPR ;
        RECT -0.0225 -0.012 0.2565 0.012 ;
    END
  END VSS
  PIN A1
    DIRECTION INPUT ;
    USE SIGNAL ;
    PORT
      LAYER M0 ;
        RECT 0.1125 0.0715 0.1995 0.0805 ;
    END
  END A1
  PIN A2
    DIRECTION INPUT ;
    USE SIGNAL ;
    PORT
      LAYER M0 ;
        RECT 0.149 0.0235 0.197 0.0325 ;
    END
  END A2
  PIN B1
    DIRECTION INPUT ;
    USE SIGNAL ;
    PORT
      LAYER M0 ;
        RECT 0.0375 0.0715 0.0855 0.0805 ;
    END
  END B1
  PIN B2
    DIRECTION INPUT ;
    USE SIGNAL ;
    PORT
      LAYER M0 ;
        RECT 0.1125 0.0075 0.1995 0.0165 ;
    END
  END B2
  PIN Y
    DIRECTION OUTPUT ;
    USE SIGNAL ;
    PORT
      LAYER M0 ;
        RECT 0.0095 0.0075 0.0575 0.0165 ;
      LAYER VSD ;
        RECT 0.015 0.0075 0.024 0.0165 ;
    END
  END Y
  OBS
    LAYER M0 ;
      RECT 0.093 0.0395 0.18 0.0485 ;
      RECT 0.0345 0.0235 0.141 0.0325 ;
  END
END gtA5_cfet_5t_32_oa22_x1_svt

MACRO gtA5_cfet_5t_32_oa31_x1_svt
  CLASS CORE ;
  ORIGIN 0 0 ;
  FOREIGN gtA5_cfet_5t_32_oa31_x1_svt 0 0 ;
  SIZE 0.234 BY 0.088 ;
  SYMMETRY X Y ;
  SITE CORESITE_5t_32 ;
  PIN VDD
    DIRECTION INOUT ;
    USE POWER ;
    SHAPE ABUTMENT ;
    PORT
      LAYER BPR ;
        RECT -0.0225 0.076 0.2565 0.1 ;
      LAYER VBPR ;
        RECT 0.0135 0.076 0.0255 0.086 ;
        RECT 0.1695 0.076 0.1815 0.086 ;
    END
  END VDD
  PIN VSS
    DIRECTION INOUT ;
    USE GROUND ;
    SHAPE ABUTMENT ;
    PORT
      LAYER BPR ;
        RECT -0.0225 -0.012 0.2565 0.012 ;
    END
  END VSS
  PIN A1
    DIRECTION INPUT ;
    USE SIGNAL ;
    PORT
      LAYER M0 ;
        RECT 0.0095 0.0715 0.0575 0.0805 ;
    END
  END A1
  PIN A2
    DIRECTION INPUT ;
    USE SIGNAL ;
    PORT
      LAYER M0 ;
        RECT 0.037 0.0235 0.085 0.0325 ;
    END
  END A2
  PIN A3
    DIRECTION INPUT ;
    USE SIGNAL ;
    PORT
      LAYER M0 ;
        RECT 0.092 0.0235 0.142 0.0325 ;
    END
  END A3
  PIN B
    DIRECTION INPUT ;
    USE SIGNAL ;
    PORT
      LAYER M0 ;
        RECT 0.1495 0.0235 0.1975 0.0325 ;
    END
  END B
  PIN Y
    DIRECTION OUTPUT ;
    USE SIGNAL ;
    PORT
      LAYER M0 ;
        RECT 0.1765 0.0715 0.2245 0.0805 ;
    END
  END Y
  OBS
    LAYER VSD ;
      RECT 0.132 0.0075 0.141 0.0165 ;
    LAYER M0 ;
      RECT 0.015 0.0075 0.1995 0.0165 ;
      RECT 0.054 0.0395 0.141 0.0485 ;
  END
END gtA5_cfet_5t_32_oa31_x1_svt

MACRO gtA5_cfet_5t_32_oa32_x1_svt
  CLASS CORE ;
  ORIGIN 0 0 ;
  FOREIGN gtA5_cfet_5t_32_oa32_x1_svt 0 0 ;
  SIZE 0.312 BY 0.088 ;
  SYMMETRY X Y ;
  SITE CORESITE_5t_32 ;
  PIN VDD
    DIRECTION INOUT ;
    USE POWER ;
    SHAPE ABUTMENT ;
    PORT
      LAYER BPR ;
        RECT -0.0225 0.076 0.3345 0.1 ;
      LAYER VBPR ;
        RECT 0.0135 0.076 0.0255 0.086 ;
        RECT 0.0915 0.076 0.1035 0.086 ;
        RECT 0.2865 0.076 0.2985 0.086 ;
    END
  END VDD
  PIN VSS
    DIRECTION INOUT ;
    USE GROUND ;
    SHAPE ABUTMENT ;
    PORT
      LAYER BPR ;
        RECT -0.0225 -0.012 0.3345 0.012 ;
    END
  END VSS
  PIN A1
    DIRECTION INPUT ;
    USE SIGNAL ;
    PORT
      LAYER M0 ;
        RECT 0.2545 0.0715 0.3025 0.0805 ;
    END
  END A1
  PIN A2
    DIRECTION INPUT ;
    USE SIGNAL ;
    PORT
      LAYER M0 ;
        RECT 0.1935 0.0715 0.2415 0.0805 ;
    END
  END A2
  PIN A3
    DIRECTION INPUT ;
    USE SIGNAL ;
    PORT
      LAYER M0 ;
        RECT 0.168 0.0555 0.216 0.0645 ;
    END
  END A3
  PIN B1
    DIRECTION INPUT ;
    USE SIGNAL ;
    PORT
      LAYER M0 ;
        RECT 0.083 0.0715 0.131 0.0805 ;
    END
  END B1
  PIN B2
    DIRECTION INPUT ;
    USE SIGNAL ;
    PORT
      LAYER M0 ;
        RECT 0.1135 0.0555 0.1615 0.0645 ;
    END
  END B2
  PIN Y
    DIRECTION OUTPUT ;
    USE SIGNAL ;
    PORT
      LAYER M0 ;
        RECT 0.023 0.0715 0.071 0.0805 ;
    END
  END Y
  OBS
    LAYER VSD ;
      RECT 0.171 0.0075 0.18 0.0165 ;
    LAYER M0 ;
      RECT 0.0345 0.0075 0.297 0.0165 ;
      RECT 0.093 0.0395 0.258 0.0485 ;
  END
END gtA5_cfet_5t_32_oa32_x1_svt

MACRO gtA5_cfet_5t_32_oa33_x1_svt
  CLASS CORE ;
  ORIGIN 0 0 ;
  FOREIGN gtA5_cfet_5t_32_oa33_x1_svt 0 0 ;
  SIZE 0.312 BY 0.088 ;
  SYMMETRY X Y ;
  SITE CORESITE_5t_32 ;
  PIN VDD
    DIRECTION INOUT ;
    USE POWER ;
    SHAPE ABUTMENT ;
    PORT
      LAYER BPR ;
        RECT -0.0225 0.076 0.3345 0.1 ;
      LAYER VBPR ;
        RECT 0.0525 0.076 0.0645 0.086 ;
        RECT 0.2865 0.076 0.2985 0.086 ;
    END
  END VDD
  PIN VSS
    DIRECTION INOUT ;
    USE GROUND ;
    SHAPE ABUTMENT ;
    PORT
      LAYER BPR ;
        RECT -0.0225 -0.012 0.3345 0.012 ;
    END
  END VSS
  PIN A1
    DIRECTION INPUT ;
    USE SIGNAL ;
    PORT
      LAYER M0 ;
        RECT 0.239 0.0235 0.287 0.0325 ;
    END
  END A1
  PIN A2
    DIRECTION INPUT ;
    USE SIGNAL ;
    PORT
      LAYER M0 ;
        RECT 0.2105 0.0555 0.2585 0.0645 ;
    END
  END A2
  PIN A3
    DIRECTION INPUT ;
    USE SIGNAL ;
    PORT
      LAYER M0 ;
        RECT 0.144 0.0235 0.1995 0.0325 ;
    END
  END A3
  PIN B1
    DIRECTION INPUT ;
    USE SIGNAL ;
    PORT
      LAYER M0 ;
        RECT 0.0375 0.0075 0.0855 0.0165 ;
    END
  END B1
  PIN B2
    DIRECTION INPUT ;
    USE SIGNAL ;
    PORT
      LAYER M0 ;
        RECT 0.0825 0.0235 0.1305 0.0325 ;
    END
  END B2
  PIN B3
    DIRECTION INPUT ;
    USE SIGNAL ;
    PORT
      LAYER M0 ;
        RECT 0.115 0.0075 0.163 0.0165 ;
    END
  END B3
  PIN Y
    DIRECTION OUTPUT ;
    USE SIGNAL ;
    PORT
      LAYER M0 ;
        RECT 0.0095 0.0395 0.0575 0.0485 ;
    END
  END Y
  OBS
    LAYER VSD ;
      RECT 0.171 0.0075 0.18 0.0165 ;
    LAYER M0 ;
      RECT 0.17 0.0075 0.297 0.0165 ;
      RECT 0.093 0.0715 0.258 0.0805 ;
      RECT 0.04 0.0555 0.194 0.0645 ;
      RECT 0.0255 0.0715 0.0735 0.0805 ;
    LAYER V0 ;
      RECT 0.1775 0.0075 0.1865 0.0165 ;
      RECT 0.1775 0.0555 0.1865 0.0645 ;
      RECT 0.0475 0.0555 0.0565 0.0645 ;
      RECT 0.0475 0.0715 0.0565 0.0805 ;
    LAYER M1 ;
      RECT 0.174 0.004 0.19 0.072 ;
      RECT 0.044 0.048 0.06 0.084 ;
  END
END gtA5_cfet_5t_32_oa33_x1_svt

MACRO gtA5_cfet_5t_32_oai211_x1_svt
  CLASS CORE ;
  ORIGIN 0 0 ;
  FOREIGN gtA5_cfet_5t_32_oai211_x1_svt 0 0 ;
  SIZE 0.195 BY 0.088 ;
  SYMMETRY X Y ;
  SITE CORESITE_5t_32 ;
  PIN VDD
    DIRECTION INOUT ;
    USE POWER ;
    SHAPE ABUTMENT ;
    PORT
      LAYER BPR ;
        RECT -0.0225 0.076 0.2175 0.1 ;
      LAYER VBPR ;
        RECT 0.0915 0.076 0.1035 0.086 ;
        RECT 0.1695 0.076 0.1815 0.086 ;
    END
  END VDD
  PIN VSS
    DIRECTION INOUT ;
    USE GROUND ;
    SHAPE ABUTMENT ;
    PORT
      LAYER BPR ;
        RECT -0.0225 -0.012 0.2175 0.012 ;
    END
  END VSS
  PIN A1
    DIRECTION INPUT ;
    USE SIGNAL ;
    PORT
      LAYER M0 ;
        RECT 0.04 0.0555 0.09 0.0645 ;
    END
  END A1
  PIN A2
    DIRECTION INPUT ;
    USE SIGNAL ;
    PORT
      LAYER M0 ;
        RECT 0.0095 0.0715 0.0575 0.0805 ;
    END
  END A2
  PIN B
    DIRECTION INPUT ;
    USE SIGNAL ;
    PORT
      LAYER M0 ;
        RECT 0.104 0.0555 0.152 0.0645 ;
    END
  END B
  PIN C
    DIRECTION INPUT ;
    USE SIGNAL ;
    PORT
      LAYER M0 ;
        RECT 0.131 0.0715 0.179 0.0805 ;
    END
  END C
  PIN Y
    DIRECTION OUTPUT ;
    USE SIGNAL ;
    PORT
      LAYER M0 ;
        RECT 0.015 0.0075 0.141 0.0165 ;
      LAYER VSD ;
        RECT 0.015 0.0075 0.024 0.0165 ;
        RECT 0.132 0.0075 0.141 0.0165 ;
    END
  END Y
  OBS
    LAYER M0 ;
      RECT 0.015 0.0395 0.102 0.0485 ;
  END
END gtA5_cfet_5t_32_oai211_x1_svt

MACRO gtA5_cfet_5t_32_oai21_x1_svt
  CLASS CORE ;
  ORIGIN 0 0 ;
  FOREIGN gtA5_cfet_5t_32_oai21_x1_svt 0 0 ;
  SIZE 0.156 BY 0.088 ;
  SYMMETRY X Y ;
  SITE CORESITE_5t_32 ;
  PIN VDD
    DIRECTION INOUT ;
    USE POWER ;
    SHAPE ABUTMENT ;
    PORT
      LAYER BPR ;
        RECT -0.0225 0.076 0.1785 0.1 ;
      LAYER VBPR ;
        RECT 0.0135 0.076 0.0255 0.086 ;
        RECT 0.1305 0.076 0.1425 0.086 ;
    END
  END VDD
  PIN VSS
    DIRECTION INOUT ;
    USE GROUND ;
    SHAPE ABUTMENT ;
    PORT
      LAYER BPR ;
        RECT -0.0225 -0.012 0.1785 0.012 ;
    END
  END VSS
  PIN A1
    DIRECTION INPUT ;
    USE SIGNAL ;
    PORT
      LAYER M0 ;
        RECT 0.054 0.0555 0.102 0.0645 ;
    END
  END A1
  PIN A2
    DIRECTION INPUT ;
    USE SIGNAL ;
    PORT
      LAYER M0 ;
        RECT 0.083 0.0715 0.131 0.0805 ;
    END
  END A2
  PIN B
    DIRECTION INPUT ;
    USE SIGNAL ;
    PORT
      LAYER M0 ;
        RECT 0.0095 0.0715 0.0575 0.0805 ;
    END
  END B
  PIN Y
    DIRECTION OUTPUT ;
    USE SIGNAL ;
    PORT
      LAYER M0 ;
        RECT 0.054 0.0075 0.102 0.0165 ;
      LAYER VSD ;
        RECT 0.054 0.0075 0.063 0.0165 ;
    END
  END Y
  OBS
    LAYER M0 ;
      RECT 0.054 0.0395 0.141 0.0485 ;
  END
END gtA5_cfet_5t_32_oai21_x1_svt

MACRO gtA5_cfet_5t_32_oai22_x1_svt
  CLASS CORE ;
  ORIGIN 0 0 ;
  FOREIGN gtA5_cfet_5t_32_oai22_x1_svt 0 0 ;
  SIZE 0.195 BY 0.088 ;
  SYMMETRY X Y ;
  SITE CORESITE_5t_32 ;
  PIN VDD
    DIRECTION INOUT ;
    USE POWER ;
    SHAPE ABUTMENT ;
    PORT
      LAYER BPR ;
        RECT -0.0225 0.076 0.2175 0.1 ;
      LAYER VBPR ;
        RECT 0.0135 0.076 0.0255 0.086 ;
        RECT 0.1695 0.076 0.1815 0.086 ;
    END
  END VDD
  PIN VSS
    DIRECTION INOUT ;
    USE GROUND ;
    SHAPE ABUTMENT ;
    PORT
      LAYER BPR ;
        RECT -0.0225 -0.012 0.2175 0.012 ;
    END
  END VSS
  PIN A1
    DIRECTION INPUT ;
    USE SIGNAL ;
    PORT
      LAYER M0 ;
        RECT 0.0095 0.0715 0.0575 0.0805 ;
    END
  END A1
  PIN A2
    DIRECTION INPUT ;
    USE SIGNAL ;
    PORT
      LAYER M0 ;
        RECT 0.071 0.0715 0.119 0.0805 ;
    END
  END A2
  PIN B1
    DIRECTION INPUT ;
    USE SIGNAL ;
    PORT
      LAYER M0 ;
        RECT 0.131 0.0555 0.179 0.0645 ;
    END
  END B1
  PIN B2
    DIRECTION INPUT ;
    USE SIGNAL ;
    PORT
      LAYER M0 ;
        RECT 0.11 0.0075 0.158 0.0165 ;
    END
  END B2
  PIN Y
    DIRECTION OUTPUT ;
    USE SIGNAL ;
    PORT
      LAYER M0 ;
        RECT 0.054 0.0075 0.102 0.0165 ;
      LAYER VSD ;
        RECT 0.093 0.0075 0.102 0.0165 ;
    END
  END Y
  OBS
    LAYER M0 ;
      RECT 0.015 0.0395 0.18 0.0485 ;
  END
END gtA5_cfet_5t_32_oai22_x1_svt

MACRO gtA5_cfet_5t_32_oai31_x1_svt
  CLASS CORE ;
  ORIGIN 0 0 ;
  FOREIGN gtA5_cfet_5t_32_oai31_x1_svt 0 0 ;
  SIZE 0.195 BY 0.088 ;
  SYMMETRY X Y ;
  SITE CORESITE_5t_32 ;
  PIN VDD
    DIRECTION INOUT ;
    USE POWER ;
    SHAPE ABUTMENT ;
    PORT
      LAYER BPR ;
        RECT -0.0225 0.076 0.2175 0.1 ;
      LAYER VBPR ;
        RECT 0.0135 0.076 0.0255 0.086 ;
        RECT 0.1695 0.076 0.1815 0.086 ;
    END
  END VDD
  PIN VSS
    DIRECTION INOUT ;
    USE GROUND ;
    SHAPE ABUTMENT ;
    PORT
      LAYER BPR ;
        RECT -0.0225 -0.012 0.2175 0.012 ;
    END
  END VSS
  PIN A1
    DIRECTION INPUT ;
    USE SIGNAL ;
    PORT
      LAYER M0 ;
        RECT 0.131 0.0715 0.179 0.0805 ;
    END
  END A1
  PIN A2
    DIRECTION INPUT ;
    USE SIGNAL ;
    PORT
      LAYER M0 ;
        RECT 0.104 0.0235 0.152 0.0325 ;
    END
  END A2
  PIN A3
    DIRECTION INPUT ;
    USE SIGNAL ;
    PORT
      LAYER M0 ;
        RECT 0.04 0.0235 0.09 0.0325 ;
    END
  END A3
  PIN B
    DIRECTION INPUT ;
    USE SIGNAL ;
    PORT
      LAYER M0 ;
        RECT 0.0095 0.0715 0.0575 0.0805 ;
    END
  END B
  PIN Y
    DIRECTION OUTPUT ;
    USE SIGNAL ;
    PORT
      LAYER M0 ;
        RECT 0.054 0.0075 0.18 0.0165 ;
      LAYER VSD ;
        RECT 0.054 0.0075 0.063 0.0165 ;
    END
  END Y
  OBS
    LAYER M0 ;
      RECT 0.054 0.0555 0.141 0.0645 ;
  END
END gtA5_cfet_5t_32_oai31_x1_svt

MACRO gtA5_cfet_5t_32_oai32_x1_svt
  CLASS CORE ;
  ORIGIN 0 0 ;
  FOREIGN gtA5_cfet_5t_32_oai32_x1_svt 0 0 ;
  SIZE 0.234 BY 0.088 ;
  SYMMETRY X Y ;
  SITE CORESITE_5t_32 ;
  PIN VDD
    DIRECTION INOUT ;
    USE POWER ;
    SHAPE ABUTMENT ;
    PORT
      LAYER BPR ;
        RECT -0.0225 0.076 0.2565 0.1 ;
      LAYER VBPR ;
        RECT 0.0915 0.076 0.1035 0.086 ;
    END
  END VDD
  PIN VSS
    DIRECTION INOUT ;
    USE GROUND ;
    SHAPE ABUTMENT ;
    PORT
      LAYER BPR ;
        RECT -0.0225 -0.012 0.2565 0.012 ;
    END
  END VSS
  PIN A1
    DIRECTION INPUT ;
    USE SIGNAL ;
    PORT
      LAYER M0 ;
        RECT 0.092 0.0075 0.142 0.0165 ;
    END
  END A1
  PIN A2
    DIRECTION INPUT ;
    USE SIGNAL ;
    PORT
      LAYER M0 ;
        RECT 0.1495 0.0075 0.1975 0.0165 ;
    END
  END A2
  PIN A3
    DIRECTION INPUT ;
    USE SIGNAL ;
    PORT
      LAYER M0 ;
        RECT 0.1765 0.0555 0.2245 0.0645 ;
    END
  END A3
  PIN B1
    DIRECTION INPUT ;
    USE SIGNAL ;
    PORT
      LAYER M0 ;
        RECT 0.037 0.0075 0.085 0.0165 ;
    END
  END B1
  PIN B2
    DIRECTION INPUT ;
    USE SIGNAL ;
    PORT
      LAYER M0 ;
        RECT 0.0095 0.0555 0.0575 0.0645 ;
    END
  END B2
  PIN Y
    DIRECTION OUTPUT ;
    USE SIGNAL ;
    PORT
      LAYER M0 ;
        RECT 0.015 0.0715 0.219 0.0805 ;
      LAYER VSD ;
        RECT 0.015 0.0715 0.024 0.0805 ;
    END
  END Y
  OBS
    LAYER M0 ;
      RECT 0.015 0.0395 0.18 0.0485 ;
  END
END gtA5_cfet_5t_32_oai32_x1_svt

MACRO gtA5_cfet_5t_32_oai33_x1_svt
  CLASS CORE ;
  ORIGIN 0 0 ;
  FOREIGN gtA5_cfet_5t_32_oai33_x1_svt 0 0 ;
  SIZE 0.273 BY 0.088 ;
  SYMMETRY X Y ;
  SITE CORESITE_5t_32 ;
  PIN VDD
    DIRECTION INOUT ;
    USE POWER ;
    SHAPE ABUTMENT ;
    PORT
      LAYER BPR ;
        RECT -0.0225 0.076 0.2955 0.1 ;
      LAYER VBPR ;
        RECT 0.1305 0.076 0.1425 0.086 ;
    END
  END VDD
  PIN VSS
    DIRECTION INOUT ;
    USE GROUND ;
    SHAPE ABUTMENT ;
    PORT
      LAYER BPR ;
        RECT -0.0225 -0.012 0.2955 0.012 ;
    END
  END VSS
  PIN A1
    DIRECTION INPUT ;
    USE SIGNAL ;
    PORT
      LAYER M0 ;
        RECT 0.092 0.0075 0.142 0.0165 ;
    END
  END A1
  PIN A2
    DIRECTION INPUT ;
    USE SIGNAL ;
    PORT
      LAYER M0 ;
        RECT 0.037 0.0075 0.085 0.0165 ;
    END
  END A2
  PIN A3
    DIRECTION INPUT ;
    USE SIGNAL ;
    PORT
      LAYER M0 ;
        RECT 0.0095 0.0235 0.0575 0.0325 ;
    END
  END A3
  PIN B1
    DIRECTION INPUT ;
    USE SIGNAL ;
    PORT
      LAYER M0 ;
        RECT 0.1495 0.0075 0.1975 0.0165 ;
    END
  END B1
  PIN B2
    DIRECTION INPUT ;
    USE SIGNAL ;
    PORT
      LAYER M0 ;
        RECT 0.1815 0.0555 0.2295 0.0645 ;
    END
  END B2
  PIN B3
    DIRECTION INPUT ;
    USE SIGNAL ;
    PORT
      LAYER M0 ;
        RECT 0.209 0.0235 0.257 0.0325 ;
    END
  END B3
  PIN Y
    DIRECTION OUTPUT ;
    USE SIGNAL ;
    PORT
      LAYER M0 ;
        RECT 0.015 0.0715 0.258 0.0805 ;
      LAYER VSD ;
        RECT 0.249 0.0715 0.258 0.0805 ;
    END
  END Y
  OBS
    LAYER M0 ;
      RECT 0.054 0.0395 0.219 0.0485 ;
  END
END gtA5_cfet_5t_32_oai33_x1_svt

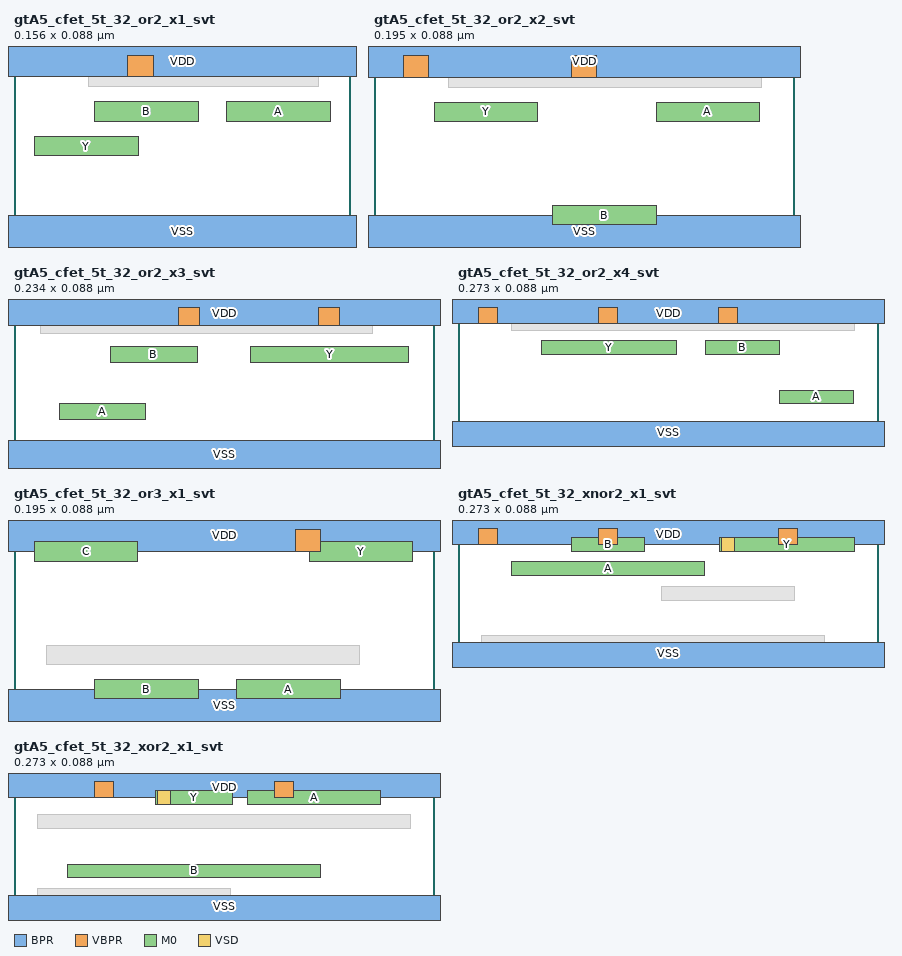
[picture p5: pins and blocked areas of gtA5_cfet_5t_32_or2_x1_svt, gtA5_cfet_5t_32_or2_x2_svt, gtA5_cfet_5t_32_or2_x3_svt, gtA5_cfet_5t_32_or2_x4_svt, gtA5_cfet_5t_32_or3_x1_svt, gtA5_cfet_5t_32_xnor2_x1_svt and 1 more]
MACRO gtA5_cfet_5t_32_or2_x1_svt
  CLASS CORE ;
  ORIGIN 0 0 ;
  FOREIGN gtA5_cfet_5t_32_or2_x1_svt 0 0 ;
  SIZE 0.156 BY 0.088 ;
  SYMMETRY X Y ;
  SITE CORESITE_5t_32 ;
  PIN VDD
    DIRECTION INOUT ;
    USE POWER ;
    SHAPE ABUTMENT ;
    PORT
      LAYER BPR ;
        RECT -0.0225 0.076 0.1785 0.1 ;
      LAYER VBPR ;
        RECT 0.0525 0.076 0.0645 0.086 ;
    END
  END VDD
  PIN VSS
    DIRECTION INOUT ;
    USE GROUND ;
    SHAPE ABUTMENT ;
    PORT
      LAYER BPR ;
        RECT -0.0225 -0.012 0.1785 0.012 ;
    END
  END VSS
  PIN A
    DIRECTION INPUT ;
    USE SIGNAL ;
    PORT
      LAYER M0 ;
        RECT 0.0985 0.0555 0.1465 0.0645 ;
    END
  END A
  PIN B
    DIRECTION INPUT ;
    USE SIGNAL ;
    PORT
      LAYER M0 ;
        RECT 0.0375 0.0555 0.0855 0.0645 ;
    END
  END B
  PIN Y
    DIRECTION OUTPUT ;
    USE SIGNAL ;
    PORT
      LAYER M0 ;
        RECT 0.0095 0.0395 0.0575 0.0485 ;
    END
  END Y
  OBS
    LAYER VSD ;
      RECT 0.132 0.0715 0.141 0.0805 ;
    LAYER M0 ;
      RECT 0.0345 0.0715 0.141 0.0805 ;
  END
END gtA5_cfet_5t_32_or2_x1_svt

MACRO gtA5_cfet_5t_32_or2_x2_svt
  CLASS CORE ;
  ORIGIN 0 0 ;
  FOREIGN gtA5_cfet_5t_32_or2_x2_svt 0 0 ;
  SIZE 0.195 BY 0.088 ;
  SYMMETRY X Y ;
  SITE CORESITE_5t_32 ;
  PIN VDD
    DIRECTION INOUT ;
    USE POWER ;
    SHAPE ABUTMENT ;
    PORT
      LAYER BPR ;
        RECT -0.0225 0.076 0.2175 0.1 ;
      LAYER VBPR ;
        RECT 0.0135 0.076 0.0255 0.086 ;
        RECT 0.0915 0.076 0.1035 0.086 ;
    END
  END VDD
  PIN VSS
    DIRECTION INOUT ;
    USE GROUND ;
    SHAPE ABUTMENT ;
    PORT
      LAYER BPR ;
        RECT -0.0225 -0.012 0.2175 0.012 ;
    END
  END VSS
  PIN A
    DIRECTION INPUT ;
    USE SIGNAL ;
    PORT
      LAYER M0 ;
        RECT 0.131 0.0555 0.179 0.0645 ;
    END
  END A
  PIN B
    DIRECTION INPUT ;
    USE SIGNAL ;
    PORT
      LAYER M0 ;
        RECT 0.083 0.0075 0.131 0.0165 ;
    END
  END B
  PIN Y
    DIRECTION OUTPUT ;
    USE SIGNAL ;
    PORT
      LAYER M0 ;
        RECT 0.028 0.0555 0.076 0.0645 ;
    END
  END Y
  OBS
    LAYER VSD ;
      RECT 0.171 0.0715 0.18 0.0805 ;
    LAYER M0 ;
      RECT 0.0345 0.0715 0.18 0.0805 ;
  END
END gtA5_cfet_5t_32_or2_x2_svt

MACRO gtA5_cfet_5t_32_or2_x3_svt
  CLASS CORE ;
  ORIGIN 0 0 ;
  FOREIGN gtA5_cfet_5t_32_or2_x3_svt 0 0 ;
  SIZE 0.234 BY 0.088 ;
  SYMMETRY X Y ;
  SITE CORESITE_5t_32 ;
  PIN VDD
    DIRECTION INOUT ;
    USE POWER ;
    SHAPE ABUTMENT ;
    PORT
      LAYER BPR ;
        RECT -0.0225 0.076 0.2565 0.1 ;
      LAYER VBPR ;
        RECT 0.0915 0.076 0.1035 0.086 ;
        RECT 0.1695 0.076 0.1815 0.086 ;
    END
  END VDD
  PIN VSS
    DIRECTION INOUT ;
    USE GROUND ;
    SHAPE ABUTMENT ;
    PORT
      LAYER BPR ;
        RECT -0.0225 -0.012 0.2565 0.012 ;
    END
  END VSS
  PIN A
    DIRECTION INPUT ;
    USE SIGNAL ;
    PORT
      LAYER M0 ;
        RECT 0.0255 0.0235 0.0735 0.0325 ;
    END
  END A
  PIN B
    DIRECTION INPUT ;
    USE SIGNAL ;
    PORT
      LAYER M0 ;
        RECT 0.054 0.0555 0.102 0.0645 ;
    END
  END B
  PIN Y
    DIRECTION OUTPUT ;
    USE SIGNAL ;
    PORT
      LAYER M0 ;
        RECT 0.132 0.0555 0.22 0.0645 ;
    END
  END Y
  OBS
    LAYER VSD ;
      RECT 0.015 0.0715 0.024 0.0805 ;
    LAYER M0 ;
      RECT 0.015 0.0715 0.1995 0.0805 ;
  END
END gtA5_cfet_5t_32_or2_x3_svt

MACRO gtA5_cfet_5t_32_or2_x4_svt
  CLASS CORE ;
  ORIGIN 0 0 ;
  FOREIGN gtA5_cfet_5t_32_or2_x4_svt 0 0 ;
  SIZE 0.273 BY 0.088 ;
  SYMMETRY X Y ;
  SITE CORESITE_5t_32 ;
  PIN VDD
    DIRECTION INOUT ;
    USE POWER ;
    SHAPE ABUTMENT ;
    PORT
      LAYER BPR ;
        RECT -0.0225 0.076 0.2955 0.1 ;
      LAYER VBPR ;
        RECT 0.0135 0.076 0.0255 0.086 ;
        RECT 0.0915 0.076 0.1035 0.086 ;
        RECT 0.1695 0.076 0.1815 0.086 ;
    END
  END VDD
  PIN VSS
    DIRECTION INOUT ;
    USE GROUND ;
    SHAPE ABUTMENT ;
    PORT
      LAYER BPR ;
        RECT -0.0225 -0.012 0.2955 0.012 ;
    END
  END VSS
  PIN A
    DIRECTION INPUT ;
    USE SIGNAL ;
    PORT
      LAYER M0 ;
        RECT 0.209 0.0235 0.257 0.0325 ;
    END
  END A
  PIN B
    DIRECTION INPUT ;
    USE SIGNAL ;
    PORT
      LAYER M0 ;
        RECT 0.161 0.0555 0.209 0.0645 ;
    END
  END B
  PIN Y
    DIRECTION OUTPUT ;
    USE SIGNAL ;
    PORT
      LAYER M0 ;
        RECT 0.054 0.0555 0.142 0.0645 ;
    END
  END Y
  OBS
    LAYER VSD ;
      RECT 0.249 0.0715 0.258 0.0805 ;
    LAYER M0 ;
      RECT 0.0345 0.0715 0.258 0.0805 ;
  END
END gtA5_cfet_5t_32_or2_x4_svt

MACRO gtA5_cfet_5t_32_or3_x1_svt
  CLASS CORE ;
  ORIGIN 0 0 ;
  FOREIGN gtA5_cfet_5t_32_or3_x1_svt 0 0 ;
  SIZE 0.195 BY 0.088 ;
  SYMMETRY X Y ;
  SITE CORESITE_5t_32 ;
  PIN VDD
    DIRECTION INOUT ;
    USE POWER ;
    SHAPE ABUTMENT ;
    PORT
      LAYER BPR ;
        RECT -0.0225 0.076 0.2175 0.1 ;
      LAYER VBPR ;
        RECT 0.1305 0.076 0.1425 0.086 ;
    END
  END VDD
  PIN VSS
    DIRECTION INOUT ;
    USE GROUND ;
    SHAPE ABUTMENT ;
    PORT
      LAYER BPR ;
        RECT -0.0225 -0.012 0.2175 0.012 ;
    END
  END VSS
  PIN A
    DIRECTION INPUT ;
    USE SIGNAL ;
    PORT
      LAYER M0 ;
        RECT 0.1035 0.0075 0.1515 0.0165 ;
    END
  END A
  PIN B
    DIRECTION INPUT ;
    USE SIGNAL ;
    PORT
      LAYER M0 ;
        RECT 0.0375 0.0075 0.0855 0.0165 ;
    END
  END B
  PIN C
    DIRECTION INPUT ;
    USE SIGNAL ;
    PORT
      LAYER M0 ;
        RECT 0.0095 0.0715 0.0575 0.0805 ;
    END
  END C
  PIN Y
    DIRECTION OUTPUT ;
    USE SIGNAL ;
    PORT
      LAYER M0 ;
        RECT 0.137 0.0715 0.185 0.0805 ;
    END
  END Y
  OBS
    LAYER M0 ;
      RECT 0.015 0.0235 0.1605 0.0325 ;
  END
END gtA5_cfet_5t_32_or3_x1_svt

MACRO gtA5_cfet_5t_32_xnor2_x1_svt
  CLASS CORE ;
  ORIGIN 0 0 ;
  FOREIGN gtA5_cfet_5t_32_xnor2_x1_svt 0 0 ;
  SIZE 0.273 BY 0.088 ;
  SYMMETRY X Y ;
  SITE CORESITE_5t_32 ;
  PIN VDD
    DIRECTION INOUT ;
    USE POWER ;
    SHAPE ABUTMENT ;
    PORT
      LAYER BPR ;
        RECT -0.0225 0.076 0.2955 0.1 ;
      LAYER VBPR ;
        RECT 0.0135 0.076 0.0255 0.086 ;
        RECT 0.0915 0.076 0.1035 0.086 ;
        RECT 0.2085 0.076 0.2205 0.086 ;
    END
  END VDD
  PIN VSS
    DIRECTION INOUT ;
    USE GROUND ;
    SHAPE ABUTMENT ;
    PORT
      LAYER BPR ;
        RECT -0.0225 -0.012 0.2955 0.012 ;
    END
  END VSS
  PIN A
    DIRECTION INPUT ;
    USE SIGNAL ;
    PORT
      LAYER M0 ;
        RECT 0.0345 0.0555 0.1605 0.0645 ;
    END
  END A
  PIN B
    DIRECTION INPUT ;
    USE SIGNAL ;
    PORT
      LAYER M0 ;
        RECT 0.0735 0.0715 0.1215 0.0805 ;
    END
  END B
  PIN Y
    DIRECTION OUTPUT ;
    USE SIGNAL ;
    PORT
      LAYER M0 ;
        RECT 0.17 0.0715 0.258 0.0805 ;
      LAYER VSD ;
        RECT 0.171 0.0715 0.18 0.0805 ;
    END
  END Y
  OBS
    LAYER VSD ;
      RECT 0.054 0.0075 0.063 0.0165 ;
    LAYER M0 ;
      RECT 0.015 0.0075 0.2385 0.0165 ;
      RECT 0.132 0.0395 0.219 0.0485 ;
  END
END gtA5_cfet_5t_32_xnor2_x1_svt

MACRO gtA5_cfet_5t_32_xor2_x1_svt
  CLASS CORE ;
  ORIGIN 0 0 ;
  FOREIGN gtA5_cfet_5t_32_xor2_x1_svt 0 0 ;
  SIZE 0.273 BY 0.088 ;
  SYMMETRY X Y ;
  SITE CORESITE_5t_32 ;
  PIN VDD
    DIRECTION INOUT ;
    USE POWER ;
    SHAPE ABUTMENT ;
    PORT
      LAYER BPR ;
        RECT -0.0225 0.076 0.2955 0.1 ;
      LAYER VBPR ;
        RECT 0.0525 0.076 0.0645 0.086 ;
        RECT 0.1695 0.076 0.1815 0.086 ;
    END
  END VDD
  PIN VSS
    DIRECTION INOUT ;
    USE GROUND ;
    SHAPE ABUTMENT ;
    PORT
      LAYER BPR ;
        RECT -0.0225 -0.012 0.2955 0.012 ;
    END
  END VSS
  PIN A
    DIRECTION INPUT ;
    USE SIGNAL ;
    PORT
      LAYER M0 ;
        RECT 0.1515 0.0715 0.2385 0.0805 ;
    END
  END A
  PIN B
    DIRECTION INPUT ;
    USE SIGNAL ;
    PORT
      LAYER M0 ;
        RECT 0.0345 0.0235 0.1995 0.0325 ;
    END
  END B
  PIN Y
    DIRECTION OUTPUT ;
    USE SIGNAL ;
    PORT
      LAYER M0 ;
        RECT 0.092 0.0715 0.142 0.0805 ;
      LAYER VSD ;
        RECT 0.093 0.0715 0.102 0.0805 ;
    END
  END Y
  OBS
    LAYER VSD ;
      RECT 0.132 0.0075 0.141 0.0165 ;
      RECT 0.015 0.0075 0.024 0.0165 ;
    LAYER M0 ;
      RECT 0.015 0.0555 0.258 0.0645 ;
      RECT 0.015 0.0075 0.141 0.0165 ;
  END
END gtA5_cfet_5t_32_xor2_x1_svt

END LIBRARY
